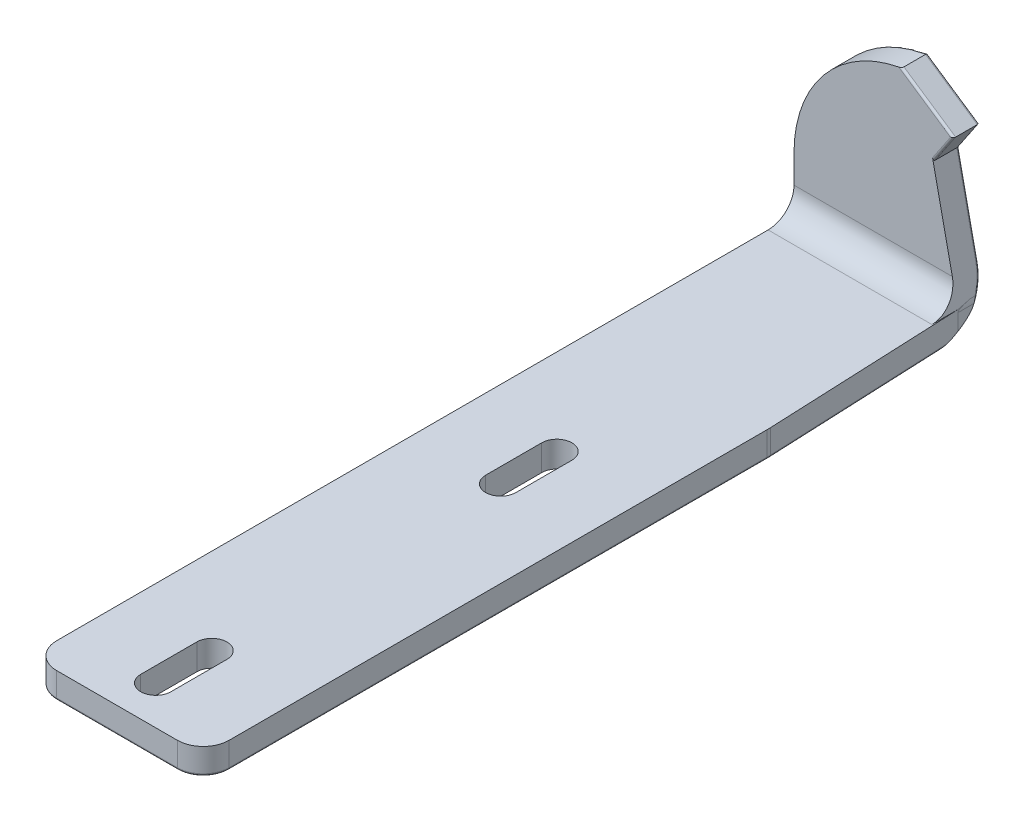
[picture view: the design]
ISO-10303-21;
HEADER;
FILE_DESCRIPTION(('STEP AP214'),'2;1');
FILE_NAME('part.step','',(''),(''),'','','');
FILE_SCHEMA(('AUTOMOTIVE_DESIGN { 1 0 10303 214 1 1 1 1 }'));
ENDSEC;
DATA;
#1=APPLICATION_CONTEXT('core data for automotive mechanical design processes');
#2=APPLICATION_PROTOCOL_DEFINITION('international standard','automotive_design',2000,#1);
#3=PRODUCT_CONTEXT('',#1,'mechanical');
#4=PRODUCT('Part','Part','',(#3));
#5=PRODUCT_RELATED_PRODUCT_CATEGORY('part','',(#4));
#6=PRODUCT_DEFINITION_FORMATION('','',#4);
#7=PRODUCT_DEFINITION_CONTEXT('part definition',#1,'design');
#8=PRODUCT_DEFINITION('design','',#6,#7);
#9=PRODUCT_DEFINITION_SHAPE('','',#8);
#10=(LENGTH_UNIT() NAMED_UNIT(*) SI_UNIT(.MILLI.,.METRE.));
#11=(NAMED_UNIT(*) PLANE_ANGLE_UNIT() SI_UNIT($,.RADIAN.));
#12=(NAMED_UNIT(*) SI_UNIT($,.STERADIAN.) SOLID_ANGLE_UNIT());
#13=UNCERTAINTY_MEASURE_WITH_UNIT(LENGTH_MEASURE(1.E-05),#10,'distance_accuracy_value','');
#14=(GEOMETRIC_REPRESENTATION_CONTEXT(3) GLOBAL_UNCERTAINTY_ASSIGNED_CONTEXT((#13)) GLOBAL_UNIT_ASSIGNED_CONTEXT((#10,
#11,#12)) REPRESENTATION_CONTEXT('',''));
#15=CARTESIAN_POINT('',(0.,0.,0.));
#16=DIRECTION('',(0.,0.,1.));
#17=DIRECTION('',(1.,0.,0.));
#18=AXIS2_PLACEMENT_3D('',#15,#16,#17);
#19=CARTESIAN_POINT('',(16.,2.68468729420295,3.));
#20=DIRECTION('',(0.,0.,-1.));
#21=DIRECTION('',(-1.,0.,0.));
#22=AXIS2_PLACEMENT_3D('',#19,#20,#21);
#23=CYLINDRICAL_SURFACE('',#22,3.);
#24=DIRECTION('',(0.,0.,-1.));
#25=VECTOR('',#24,1.);
#26=CARTESIAN_POINT('',(18.9344428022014,3.30842236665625,3.));
#27=LINE('',#26,#25);
#28=CARTESIAN_POINT('',(18.9344428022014,3.30842236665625,1.49849331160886));
#29=VERTEX_POINT('',#28);
#30=CARTESIAN_POINT('',(18.9344428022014,3.30842236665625,0.946743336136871));
#31=VERTEX_POINT('',#30);
#32=EDGE_CURVE('E540',#29,#31,#27,.T.);
#33=ORIENTED_EDGE('',*,*,#32,.F.);
#34=CARTESIAN_POINT('',(16.,2.68468729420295,-65.7112966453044));
#35=DIRECTION('',(-0.999048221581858,0.,0.0436193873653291));
#36=DIRECTION('',(-0.0436193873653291,0.,-0.999048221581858));
#37=AXIS2_PLACEMENT_3D('',#34,#35,#36);
#38=ELLIPSE('',#37,68.7767568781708,3.);
#39=CARTESIAN_POINT('',(19.,2.68468729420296,3.));
#40=VERTEX_POINT('',#39);
#41=EDGE_CURVE('E543',#29,#40,#38,.F.);
#42=ORIENTED_EDGE('',*,*,#41,.T.);
#43=DIRECTION('',(0.,0.,-1.));
#44=VECTOR('',#43,1.);
#45=CARTESIAN_POINT('',(19.,2.68468729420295,3.));
#46=LINE('',#45,#44);
#47=CARTESIAN_POINT('',(19.,2.68468729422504,1.12447066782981));
#48=VERTEX_POINT('',#47);
#49=EDGE_CURVE('E548',#48,#40,#46,.F.);
#50=ORIENTED_EDGE('',*,*,#49,.F.);
#51=CARTESIAN_POINT('',(17.1290818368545,11.8019779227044,6.));
#52=CARTESIAN_POINT('',(17.0869909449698,12.,6.));
#53=CARTESIAN_POINT('',(16.884544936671,12.,6.));
#54=CARTESIAN_POINT('',(17.1290818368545,11.8019779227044,5.74907725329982));
#55=CARTESIAN_POINT('',(17.0869909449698,12.,5.74004591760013));
#56=CARTESIAN_POINT('',(16.884544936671,12.,5.73816756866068));
#57=CARTESIAN_POINT('',(17.1325789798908,11.7855251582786,5.49815450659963));
#58=CARTESIAN_POINT('',(17.0905911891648,11.9830621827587,5.47996382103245));
#59=CARTESIAN_POINT('',(16.8880420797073,11.9828318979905,5.47633513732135));
#60=CARTESIAN_POINT('',(17.1465021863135,11.7200216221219,5.00060461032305));
#61=CARTESIAN_POINT('',(17.1049124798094,11.9156858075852,4.96442597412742));
#62=CARTESIAN_POINT('',(16.90196528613,11.9144803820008,4.95715263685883));
#63=CARTESIAN_POINT('',(17.1569335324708,11.670945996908,4.75398088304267));
#64=CARTESIAN_POINT('',(17.1156529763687,11.8651557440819,4.70872615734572));
#65=CARTESIAN_POINT('',(16.9123966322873,11.8632710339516,4.69980613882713));
#66=CARTESIAN_POINT('',(17.1845413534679,11.5410614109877,4.2692439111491));
#67=CARTESIAN_POINT('',(17.144057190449,11.7315244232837,4.20622729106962));
#68=CARTESIAN_POINT('',(16.9400044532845,11.7277392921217,4.19399364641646));
#69=CARTESIAN_POINT('',(17.2017277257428,11.4602058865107,4.03114371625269));
#70=CARTESIAN_POINT('',(17.1617582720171,11.648247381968,3.95921887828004));
#71=CARTESIAN_POINT('',(16.9571908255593,11.6433683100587,3.94554126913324));
#72=CARTESIAN_POINT('',(17.2425471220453,11.2681657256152,3.56751672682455));
#73=CARTESIAN_POINT('',(17.2037726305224,11.4505853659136,3.47821302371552));
#74=CARTESIAN_POINT('',(16.9980102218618,11.4429785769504,3.46175658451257));
#75=CARTESIAN_POINT('',(17.2661934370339,11.1569185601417,3.34201702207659));
#76=CARTESIAN_POINT('',(17.2281382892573,11.3359539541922,3.24406029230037));
#77=CARTESIAN_POINT('',(17.0216565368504,11.3268945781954,3.22645254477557));
#78=CARTESIAN_POINT('',(17.3195251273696,10.9060126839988,2.90743435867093));
#79=CARTESIAN_POINT('',(17.2830634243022,11.0775515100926,2.79264800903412));
#80=CARTESIAN_POINT('',(17.0749882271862,11.0650797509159,2.77297498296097));
#81=CARTESIAN_POINT('',(17.3492256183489,10.7662828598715,2.6983943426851));
#82=CARTESIAN_POINT('',(17.3136863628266,10.9334819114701,2.57530154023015));
#83=CARTESIAN_POINT('',(17.1046887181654,10.9192747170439,2.55484627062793));
#84=CARTESIAN_POINT('',(17.414156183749,10.4608085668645,2.30029166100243));
#85=CARTESIAN_POINT('',(17.3806078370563,10.6186411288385,2.16109729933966));
#86=CARTESIAN_POINT('',(17.1696192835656,10.6005189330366,2.13943477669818));
#87=CARTESIAN_POINT('',(17.4494015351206,10.2949922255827,2.11128667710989));
#88=CARTESIAN_POINT('',(17.4169763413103,10.447540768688,1.96422919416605));
#89=CARTESIAN_POINT('',(17.2048646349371,10.4274931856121,1.94221218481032));
#90=CARTESIAN_POINT('',(17.5248191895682,9.94018005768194,1.75647379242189));
#91=CARTESIAN_POINT('',(17.4947796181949,10.0815051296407,1.59423718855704));
#92=CARTESIAN_POINT('',(17.2802822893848,10.0572544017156,1.57197265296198));
#93=CARTESIAN_POINT('',(17.5650054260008,9.75111867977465,1.59073445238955));
#94=CARTESIAN_POINT('',(17.5362860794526,9.88623258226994,1.42118138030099));
#95=CARTESIAN_POINT('',(17.3204685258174,9.85997296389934,1.39902725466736));
#96=CARTESIAN_POINT('',(17.6496191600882,9.3530423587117,1.28527915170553));
#97=CARTESIAN_POINT('',(17.6236746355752,9.47510174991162,1.10168170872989));
#98=CARTESIAN_POINT('',(17.4050822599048,9.44458897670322,1.08029128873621));
#99=CARTESIAN_POINT('',(17.6940581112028,9.14397353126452,1.14563663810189));
#100=CARTESIAN_POINT('',(17.6696255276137,9.25891979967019,0.955380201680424));
#101=CARTESIAN_POINT('',(17.4495212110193,9.22643020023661,0.934577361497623));
#102=CARTESIAN_POINT('',(17.7864198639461,8.70944564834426,0.894761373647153));
#103=CARTESIAN_POINT('',(17.7651417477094,8.80955131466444,0.691827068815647));
#104=CARTESIAN_POINT('',(17.5418829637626,8.77300980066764,0.672794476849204));
#105=CARTESIAN_POINT('',(17.8343510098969,8.48394733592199,0.783599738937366));
#106=CARTESIAN_POINT('',(17.8147688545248,8.57607413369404,0.574782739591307));
#107=CARTESIAN_POINT('',(17.5898141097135,8.53770721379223,0.556799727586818));
#108=CARTESIAN_POINT('',(17.93288048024,8.02040262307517,0.591592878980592));
#109=CARTESIAN_POINT('',(17.9168173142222,8.09597387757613,0.371715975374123));
#110=CARTESIAN_POINT('',(17.6883435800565,8.05400838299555,0.356444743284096));
#111=CARTESIAN_POINT('',(17.9834839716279,7.7823319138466,0.510809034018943));
#112=CARTESIAN_POINT('',(17.9692900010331,7.84910929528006,0.285952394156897));
#113=CARTESIAN_POINT('',(17.7389470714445,7.80558677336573,0.272148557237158));
#114=CARTESIAN_POINT('',(18.0864956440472,7.29770009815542,0.380952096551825));
#115=CARTESIAN_POINT('',(18.076162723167,7.34631266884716,0.146923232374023));
#116=CARTESIAN_POINT('',(17.8419587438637,7.29988400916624,0.136645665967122));
#117=CARTESIAN_POINT('',(18.138906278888,7.0511274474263,0.331924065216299));
#118=CARTESIAN_POINT('',(18.1306010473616,7.09020048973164,0.0939517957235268));
#119=CARTESIAN_POINT('',(17.8943693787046,7.04259080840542,0.085485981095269));
#120=CARTESIAN_POINT('',(18.2446382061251,6.55369783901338,0.266436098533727));
#121=CARTESIAN_POINT('',(18.2405043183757,6.57314625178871,0.0214634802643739));
#122=CARTESIAN_POINT('',(18.0001013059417,6.52353382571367,0.0171507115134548));
#123=CARTESIAN_POINT('',(18.2979601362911,6.30283788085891,0.25));
#124=CARTESIAN_POINT('',(18.2959927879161,6.31209352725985,0.00225799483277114));
#125=CARTESIAN_POINT('',(18.0534232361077,6.26176691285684,0.));
#126=CARTESIAN_POINT('',(18.4046039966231,5.80111796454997,0.25));
#127=CARTESIAN_POINT('',(18.407075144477,5.78949212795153,-0.00227856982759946));
#128=CARTESIAN_POINT('',(18.1600670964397,5.73823308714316,0.));
#129=CARTESIAN_POINT('',(18.4579259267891,5.55025800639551,0.266436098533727));
#130=CARTESIAN_POINT('',(18.4626769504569,5.52790619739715,0.0127001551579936));
#131=CARTESIAN_POINT('',(18.2133890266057,5.47646617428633,0.0171507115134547));
#132=CARTESIAN_POINT('',(18.5636578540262,5.05282839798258,0.331924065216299));
#133=CARTESIAN_POINT('',(18.5730579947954,5.0086042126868,0.076404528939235));
#134=CARTESIAN_POINT('',(18.3191209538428,4.95740919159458,0.0854859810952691));
#135=CARTESIAN_POINT('',(18.6160684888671,4.80625574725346,0.380952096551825));
#136=CARTESIAN_POINT('',(18.6278295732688,4.75092419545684,0.125419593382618));
#137=CARTESIAN_POINT('',(18.3715315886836,4.70011599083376,0.136645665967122));
#138=CARTESIAN_POINT('',(18.7190801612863,4.32162393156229,0.510809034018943));
#139=CARTESIAN_POINT('',(18.7356293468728,4.24376613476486,0.256517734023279));
#140=CARTESIAN_POINT('',(18.4745432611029,4.19441322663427,0.272148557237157));
#141=CARTESIAN_POINT('',(18.7696836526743,4.08355322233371,0.591592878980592));
#142=CARTESIAN_POINT('',(18.7886351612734,3.99439338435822,0.3388518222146));
#143=CARTESIAN_POINT('',(18.5251467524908,3.94599161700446,0.356444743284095));
#144=CARTESIAN_POINT('',(18.8682131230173,3.62000850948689,0.783599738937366));
#145=CARTESIAN_POINT('',(18.8920038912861,3.50808174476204,0.535360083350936));
#146=CARTESIAN_POINT('',(18.6236762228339,3.46229278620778,0.556799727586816));
#147=CARTESIAN_POINT('',(18.9161442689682,3.39451019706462,0.894761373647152));
#148=CARTESIAN_POINT('',(18.9423313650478,3.27130959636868,0.649730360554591));
#149=CARTESIAN_POINT('',(18.6716073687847,3.22699019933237,0.672794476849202));
#150=CARTESIAN_POINT('',(19.0085060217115,2.95998231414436,1.14563663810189));
#151=CARTESIAN_POINT('',(19.0394794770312,2.81426366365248,0.908543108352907));
#152=CARTESIAN_POINT('',(18.763969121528,2.77356979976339,0.934577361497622));
#153=CARTESIAN_POINT('',(19.052944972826,2.75091348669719,1.28527915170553));
#154=CARTESIAN_POINT('',(19.0862540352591,2.59420666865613,1.05311256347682));
#155=CARTESIAN_POINT('',(18.8084080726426,2.55541102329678,1.08029128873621));
#156=CARTESIAN_POINT('',(19.1375587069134,2.35283716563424,1.59073445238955));
#157=CARTESIAN_POINT('',(19.1754823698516,2.17442035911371,1.37003190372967));
#158=CARTESIAN_POINT('',(18.89302180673,2.14002703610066,1.39902725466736));
#159=CARTESIAN_POINT('',(19.177744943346,2.16377578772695,1.75647379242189));
#160=CARTESIAN_POINT('',(19.2178825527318,1.97494318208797,1.54242861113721));
#161=CARTESIAN_POINT('',(18.9332080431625,1.94274559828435,1.57197265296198));
#162=CARTESIAN_POINT('',(19.2531625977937,1.80896361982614,2.11128667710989));
#163=CARTESIAN_POINT('',(19.2976126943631,1.59984235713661,1.91221077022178));
#164=CARTESIAN_POINT('',(19.0086256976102,1.57250681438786,1.94221218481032));
#165=CARTESIAN_POINT('',(19.2884079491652,1.64314727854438,2.30029166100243));
#166=CARTESIAN_POINT('',(19.3348852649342,1.42448869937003,2.10955596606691));
#167=CARTESIAN_POINT('',(19.0438710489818,1.39948106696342,2.13943477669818));
#168=CARTESIAN_POINT('',(19.3533385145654,1.33767298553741,2.6983943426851));
#169=CARTESIAN_POINT('',(19.4036897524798,1.10078903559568,2.52597655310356));
#170=CARTESIAN_POINT('',(19.1088016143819,1.08072528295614,2.55484627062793));
#171=CARTESIAN_POINT('',(19.3830390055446,1.19794316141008,2.90743435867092));
#172=CARTESIAN_POINT('',(19.4351646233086,0.952711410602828,2.74492276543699));
#173=CARTESIAN_POINT('',(19.1385021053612,0.934920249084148,2.77297498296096));
#174=CARTESIAN_POINT('',(19.4363706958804,0.947037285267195,3.34201702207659));
#175=CARTESIAN_POINT('',(19.4917965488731,0.686279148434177,3.200863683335));
#176=CARTESIAN_POINT('',(19.1918337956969,0.673105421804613,3.22645254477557));
#177=CARTESIAN_POINT('',(19.460017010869,0.835790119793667,3.56751672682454));
#178=CARTESIAN_POINT('',(19.5169011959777,0.568171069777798,3.43764427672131));
#179=CARTESIAN_POINT('',(19.2154801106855,0.557021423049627,3.46175658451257));
#180=CARTESIAN_POINT('',(19.5008364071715,0.643749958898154,4.03114371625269));
#181=CARTESIAN_POINT('',(19.5603223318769,0.363890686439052,3.92520493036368));
#182=CARTESIAN_POINT('',(19.256299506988,0.356631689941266,3.94554126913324));
#183=CARTESIAN_POINT('',(19.5180227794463,0.562894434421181,4.2692439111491));
#184=CARTESIAN_POINT('',(19.5785951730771,0.277923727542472,4.17569613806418));
#185=CARTESIAN_POINT('',(19.2734858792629,0.272260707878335,4.19399364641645));
#186=CARTESIAN_POINT('',(19.5456306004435,0.433009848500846,4.75398088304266));
#187=CARTESIAN_POINT('',(19.6080013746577,0.139578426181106,4.68633047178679));
#188=CARTESIAN_POINT('',(19.30109370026,0.13672896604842,4.69980613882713));
#189=CARTESIAN_POINT('',(19.5560619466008,0.383934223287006,5.00060461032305));
#190=CARTESIAN_POINT('',(19.6191034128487,0.0873474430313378,4.94612616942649));
#191=CARTESIAN_POINT('',(19.3115250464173,0.0855196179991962,4.95715263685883));
#192=CARTESIAN_POINT('',(19.5699851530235,0.318430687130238,5.49815450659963));
#193=CARTESIAN_POINT('',(19.6339457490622,0.0175197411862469,5.47080484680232));
#194=CARTESIAN_POINT('',(19.32544825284,0.0171681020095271,5.47633513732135));
#195=CARTESIAN_POINT('',(19.5734822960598,0.301977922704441,5.74907725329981));
#196=CARTESIAN_POINT('',(19.6376696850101,0.,5.73530300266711));
#197=CARTESIAN_POINT('',(19.3289453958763,0.,5.73816756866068));
#198=CARTESIAN_POINT('',(19.5734822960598,0.301977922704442,6.25092274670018));
#199=CARTESIAN_POINT('',(19.6376696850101,0.,6.26469699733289));
#200=CARTESIAN_POINT('',(19.3289453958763,0.,6.26183243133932));
#201=CARTESIAN_POINT('',(19.5699851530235,0.318430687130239,6.50184549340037));
#202=CARTESIAN_POINT('',(19.6339457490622,0.0175197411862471,6.52919515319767));
#203=CARTESIAN_POINT('',(19.32544825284,0.0171681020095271,6.52366486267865));
#204=CARTESIAN_POINT('',(19.5560619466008,0.383934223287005,6.99939538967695));
#205=CARTESIAN_POINT('',(19.6191034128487,0.0873474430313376,7.05387383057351));
#206=CARTESIAN_POINT('',(19.3115250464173,0.0855196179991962,7.04284736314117));
#207=CARTESIAN_POINT('',(19.5456306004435,0.433009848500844,7.24601911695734));
#208=CARTESIAN_POINT('',(19.6080013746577,0.139578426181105,7.31366952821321));
#209=CARTESIAN_POINT('',(19.30109370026,0.13672896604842,7.30019386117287));
#210=CARTESIAN_POINT('',(19.5180227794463,0.562894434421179,7.7307560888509));
#211=CARTESIAN_POINT('',(19.5785951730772,0.277923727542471,7.82430386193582));
#212=CARTESIAN_POINT('',(19.2734858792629,0.272260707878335,7.80600635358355));
#213=CARTESIAN_POINT('',(19.5008364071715,0.643749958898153,7.96885628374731));
#214=CARTESIAN_POINT('',(19.5603223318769,0.363890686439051,8.07479506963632));
#215=CARTESIAN_POINT('',(19.256299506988,0.356631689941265,8.05445873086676));
#216=CARTESIAN_POINT('',(19.460017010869,0.835790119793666,8.43248327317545));
#217=CARTESIAN_POINT('',(19.5169011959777,0.568171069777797,8.56235572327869));
#218=CARTESIAN_POINT('',(19.2154801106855,0.557021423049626,8.53824341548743));
#219=CARTESIAN_POINT('',(19.4363706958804,0.947037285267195,8.65798297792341));
#220=CARTESIAN_POINT('',(19.4917965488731,0.686279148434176,8.799136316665));
#221=CARTESIAN_POINT('',(19.1918337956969,0.673105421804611,8.77354745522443));
#222=CARTESIAN_POINT('',(19.3830390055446,1.19794316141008,9.09256564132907));
#223=CARTESIAN_POINT('',(19.4351646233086,0.952711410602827,9.25507723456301));
#224=CARTESIAN_POINT('',(19.1385021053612,0.934920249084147,9.22702501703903));
#225=CARTESIAN_POINT('',(19.3533385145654,1.33767298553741,9.3016056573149));
#226=CARTESIAN_POINT('',(19.4036897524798,1.10078903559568,9.47402344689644));
#227=CARTESIAN_POINT('',(19.1088016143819,1.08072528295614,9.44515372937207));
#228=CARTESIAN_POINT('',(19.2884079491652,1.64314727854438,9.69970833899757));
#229=CARTESIAN_POINT('',(19.3348852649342,1.42448869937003,9.89044403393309));
#230=CARTESIAN_POINT('',(19.0438710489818,1.39948106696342,9.86056522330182));
#231=CARTESIAN_POINT('',(19.2531625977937,1.80896361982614,9.88871332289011));
#232=CARTESIAN_POINT('',(19.2976126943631,1.59984235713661,10.0877892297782));
#233=CARTESIAN_POINT('',(19.0086256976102,1.57250681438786,10.0577878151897));
#234=CARTESIAN_POINT('',(19.177744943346,2.16377578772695,10.2435262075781));
#235=CARTESIAN_POINT('',(19.2178825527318,1.97494318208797,10.4575713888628));
#236=CARTESIAN_POINT('',(18.9332080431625,1.94274559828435,10.428027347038));
#237=CARTESIAN_POINT('',(19.1375587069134,2.35283716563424,10.4092655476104));
#238=CARTESIAN_POINT('',(19.1754823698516,2.17442035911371,10.6299680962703));
#239=CARTESIAN_POINT('',(18.89302180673,2.14002703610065,10.6009727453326));
#240=CARTESIAN_POINT('',(19.052944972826,2.75091348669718,10.7147208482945));
#241=CARTESIAN_POINT('',(19.0862540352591,2.59420666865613,10.9468874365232));
#242=CARTESIAN_POINT('',(18.8084080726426,2.55541102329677,10.9197087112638));
#243=CARTESIAN_POINT('',(19.0085060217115,2.95998231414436,10.8543633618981));
#244=CARTESIAN_POINT('',(19.0394794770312,2.81426366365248,11.0914568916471));
#245=CARTESIAN_POINT('',(18.763969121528,2.77356979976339,11.0654226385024));
#246=CARTESIAN_POINT('',(18.9161442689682,3.39451019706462,11.1052386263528));
#247=CARTESIAN_POINT('',(18.9423313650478,3.27130959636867,11.3502696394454));
#248=CARTESIAN_POINT('',(18.6716073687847,3.22699019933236,11.3272055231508));
#249=CARTESIAN_POINT('',(18.8682131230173,3.62000850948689,11.2164002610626));
#250=CARTESIAN_POINT('',(18.8920038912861,3.50808174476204,11.4646399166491));
#251=CARTESIAN_POINT('',(18.6236762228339,3.46229278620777,11.4432002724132));
#252=CARTESIAN_POINT('',(18.7696836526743,4.08355322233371,11.4084071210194));
#253=CARTESIAN_POINT('',(18.7886351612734,3.99439338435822,11.6611481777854));
#254=CARTESIAN_POINT('',(18.5251467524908,3.94599161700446,11.6435552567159));
#255=CARTESIAN_POINT('',(18.7190801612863,4.32162393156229,11.4891909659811));
#256=CARTESIAN_POINT('',(18.7356293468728,4.24376613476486,11.7434822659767));
#257=CARTESIAN_POINT('',(18.4745432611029,4.19441322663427,11.7278514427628));
#258=CARTESIAN_POINT('',(18.6160684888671,4.80625574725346,11.6190479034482));
#259=CARTESIAN_POINT('',(18.6278295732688,4.75092419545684,11.8745804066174));
#260=CARTESIAN_POINT('',(18.3715315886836,4.70011599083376,11.8633543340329));
#261=CARTESIAN_POINT('',(18.5636578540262,5.05282839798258,11.6680759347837));
#262=CARTESIAN_POINT('',(18.5730579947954,5.0086042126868,11.9235954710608));
#263=CARTESIAN_POINT('',(18.3191209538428,4.95740919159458,11.9145140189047));
#264=CARTESIAN_POINT('',(18.4579259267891,5.55025800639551,11.7335639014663));
#265=CARTESIAN_POINT('',(18.4626769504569,5.52790619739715,11.987299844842));
#266=CARTESIAN_POINT('',(18.2133890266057,5.47646617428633,11.9828492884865));
#267=CARTESIAN_POINT('',(18.4046039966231,5.80111796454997,11.75));
#268=CARTESIAN_POINT('',(18.407075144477,5.78949212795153,12.0022785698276));
#269=CARTESIAN_POINT('',(18.1600670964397,5.73823308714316,12.));
#270=CARTESIAN_POINT('',(18.2979601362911,6.30283788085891,11.75));
#271=CARTESIAN_POINT('',(18.2959927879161,6.31209352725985,11.9977420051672));
#272=CARTESIAN_POINT('',(18.0534232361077,6.26176691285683,12.));
#273=CARTESIAN_POINT('',(18.2446382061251,6.55369783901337,11.7335639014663));
#274=CARTESIAN_POINT('',(18.2405043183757,6.57314625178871,11.9785365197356));
#275=CARTESIAN_POINT('',(18.0001013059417,6.52353382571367,11.9828492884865));
#276=CARTESIAN_POINT('',(18.138906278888,7.0511274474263,11.6680759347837));
#277=CARTESIAN_POINT('',(18.1306010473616,7.09020048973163,11.9060482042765));
#278=CARTESIAN_POINT('',(17.8943693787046,7.04259080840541,11.9145140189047));
#279=CARTESIAN_POINT('',(18.0864956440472,7.29770009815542,11.6190479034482));
#280=CARTESIAN_POINT('',(18.076162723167,7.34631266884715,11.853076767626));
#281=CARTESIAN_POINT('',(17.8419587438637,7.29988400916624,11.8633543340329));
#282=CARTESIAN_POINT('',(17.9834839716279,7.78233191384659,11.4891909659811));
#283=CARTESIAN_POINT('',(17.9692900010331,7.84910929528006,11.7140476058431));
#284=CARTESIAN_POINT('',(17.7389470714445,7.80558677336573,11.7278514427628));
#285=CARTESIAN_POINT('',(17.93288048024,8.02040262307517,11.4084071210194));
#286=CARTESIAN_POINT('',(17.9168173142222,8.09597387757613,11.6282840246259));
#287=CARTESIAN_POINT('',(17.6883435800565,8.05400838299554,11.6435552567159));
#288=CARTESIAN_POINT('',(17.8343510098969,8.48394733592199,11.2164002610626));
#289=CARTESIAN_POINT('',(17.8147688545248,8.57607413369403,11.4252172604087));
#290=CARTESIAN_POINT('',(17.5898141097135,8.53770721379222,11.4432002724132));
#291=CARTESIAN_POINT('',(17.7864198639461,8.70944564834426,11.1052386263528));
#292=CARTESIAN_POINT('',(17.7651417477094,8.80955131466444,11.3081729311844));
#293=CARTESIAN_POINT('',(17.5418829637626,8.77300980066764,11.3272055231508));
#294=CARTESIAN_POINT('',(17.6940581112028,9.14397353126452,10.8543633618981));
#295=CARTESIAN_POINT('',(17.6696255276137,9.25891979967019,11.0446197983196));
#296=CARTESIAN_POINT('',(17.4495212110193,9.22643020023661,11.0654226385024));
#297=CARTESIAN_POINT('',(17.6496191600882,9.35304235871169,10.7147208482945));
#298=CARTESIAN_POINT('',(17.6236746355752,9.47510174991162,10.8983182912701));
#299=CARTESIAN_POINT('',(17.4050822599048,9.44458897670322,10.9197087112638));
#300=CARTESIAN_POINT('',(17.5650054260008,9.75111867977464,10.4092655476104));
#301=CARTESIAN_POINT('',(17.5362860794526,9.88623258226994,10.578818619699));
#302=CARTESIAN_POINT('',(17.3204685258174,9.85997296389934,10.6009727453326));
#303=CARTESIAN_POINT('',(17.5248191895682,9.94018005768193,10.2435262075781));
#304=CARTESIAN_POINT('',(17.4947796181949,10.0815051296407,10.405762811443));
#305=CARTESIAN_POINT('',(17.2802822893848,10.0572544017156,10.428027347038));
#306=CARTESIAN_POINT('',(17.4494015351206,10.2949922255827,9.88871332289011));
#307=CARTESIAN_POINT('',(17.4169763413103,10.447540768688,10.035770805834));
#308=CARTESIAN_POINT('',(17.2048646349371,10.4274931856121,10.0577878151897));
#309=CARTESIAN_POINT('',(17.414156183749,10.4608085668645,9.69970833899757));
#310=CARTESIAN_POINT('',(17.3806078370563,10.6186411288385,9.83890270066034));
#311=CARTESIAN_POINT('',(17.1696192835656,10.6005189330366,9.86056522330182));
#312=CARTESIAN_POINT('',(17.3492256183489,10.7662828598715,9.30160565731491));
#313=CARTESIAN_POINT('',(17.3136863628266,10.93348191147,9.42469845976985));
#314=CARTESIAN_POINT('',(17.1046887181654,10.9192747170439,9.44515372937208));
#315=CARTESIAN_POINT('',(17.3195251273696,10.9060126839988,9.09256564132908));
#316=CARTESIAN_POINT('',(17.2830634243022,11.0775515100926,9.20735199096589));
#317=CARTESIAN_POINT('',(17.0749882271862,11.0650797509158,9.22702501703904));
#318=CARTESIAN_POINT('',(17.2661934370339,11.1569185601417,8.65798297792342));
#319=CARTESIAN_POINT('',(17.2281382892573,11.3359539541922,8.75593970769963));
#320=CARTESIAN_POINT('',(17.0216565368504,11.3268945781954,8.77354745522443));
#321=CARTESIAN_POINT('',(17.2425471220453,11.2681657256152,8.43248327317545));
#322=CARTESIAN_POINT('',(17.2037726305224,11.4505853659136,8.52178697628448));
#323=CARTESIAN_POINT('',(16.9980102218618,11.4429785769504,8.53824341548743));
#324=CARTESIAN_POINT('',(17.2017277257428,11.4602058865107,7.96885628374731));
#325=CARTESIAN_POINT('',(17.1617582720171,11.648247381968,8.04078112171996));
#326=CARTESIAN_POINT('',(16.9571908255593,11.6433683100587,8.05445873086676));
#327=CARTESIAN_POINT('',(17.1845413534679,11.5410614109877,7.7307560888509));
#328=CARTESIAN_POINT('',(17.144057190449,11.7315244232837,7.79377270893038));
#329=CARTESIAN_POINT('',(16.9400044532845,11.7277392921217,7.80600635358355));
#330=CARTESIAN_POINT('',(17.1569335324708,11.670945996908,7.24601911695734));
#331=CARTESIAN_POINT('',(17.1156529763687,11.8651557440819,7.29127384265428));
#332=CARTESIAN_POINT('',(16.9123966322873,11.8632710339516,7.30019386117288));
#333=CARTESIAN_POINT('',(17.1465021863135,11.7200216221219,6.99939538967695));
#334=CARTESIAN_POINT('',(17.1049124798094,11.9156858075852,7.03557402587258));
#335=CARTESIAN_POINT('',(16.90196528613,11.9144803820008,7.04284736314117));
#336=CARTESIAN_POINT('',(17.1325789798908,11.7855251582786,6.50184549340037));
#337=CARTESIAN_POINT('',(17.0905911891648,11.9830621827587,6.52003617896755));
#338=CARTESIAN_POINT('',(16.8880420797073,11.9828318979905,6.52366486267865));
#339=CARTESIAN_POINT('',(17.1290818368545,11.8019779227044,6.25092274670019));
#340=CARTESIAN_POINT('',(17.0869909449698,12.,6.25995408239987));
#341=CARTESIAN_POINT('',(16.884544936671,12.,6.26183243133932));
#342=CARTESIAN_POINT('',(17.1290818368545,11.8019779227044,6.));
#343=CARTESIAN_POINT('',(17.0869909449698,12.,6.));
#344=CARTESIAN_POINT('',(16.884544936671,12.,6.));
#345=(BOUNDED_SURFACE() B_SPLINE_SURFACE(3,2,((#51,#52,#53),(#54,#55,#56),(#57,#58,#59),(#60,
#61,#62),(#63,#64,#65),(#66,#67,#68),(#69,#70,#71),(#72,#73,#74),(#75,#76,#77),(#78,#79,#80),
(#81,#82,#83),(#84,#85,#86),(#87,#88,#89),(#90,#91,#92),(#93,#94,#95),(#96,#97,#98),(#99,#100,
#101),(#102,#103,#104),(#105,#106,#107),(#108,#109,#110),(#111,#112,#113),(#114,#115,#116),
(#117,#118,#119),(#120,#121,#122),(#123,#124,#125),(#126,#127,#128),(#129,#130,#131),(#132,#133,
#134),(#135,#136,#137),(#138,#139,#140),(#141,#142,#143),(#144,#145,#146),(#147,#148,#149),
(#150,#151,#152),(#153,#154,#155),(#156,#157,#158),(#159,#160,#161),(#162,#163,#164),(#165,#166,
#167),(#168,#169,#170),(#171,#172,#173),(#174,#175,#176),(#177,#178,#179),(#180,#181,#182),
(#183,#184,#185),(#186,#187,#188),(#189,#190,#191),(#192,#193,#194),(#195,#196,#197),(#198,#199,
#200),(#201,#202,#203),(#204,#205,#206),(#207,#208,#209),(#210,#211,#212),(#213,#214,#215),
(#216,#217,#218),(#219,#220,#221),(#222,#223,#224),(#225,#226,#227),(#228,#229,#230),(#231,#232,
#233),(#234,#235,#236),(#237,#238,#239),(#240,#241,#242),(#243,#244,#245),(#246,#247,#248),
(#249,#250,#251),(#252,#253,#254),(#255,#256,#257),(#258,#259,#260),(#261,#262,#263),(#264,#265,
#266),(#267,#268,#269),(#270,#271,#272),(#273,#274,#275),(#276,#277,#278),(#279,#280,#281),
(#282,#283,#284),(#285,#286,#287),(#288,#289,#290),(#291,#292,#293),(#294,#295,#296),(#297,#298,
#299),(#300,#301,#302),(#303,#304,#305),(#306,#307,#308),(#309,#310,#311),(#312,#313,#314),
(#315,#316,#317),(#318,#319,#320),(#321,#322,#323),(#324,#325,#326),(#327,#328,#329),(#330,#331,
#332),(#333,#334,#335),(#336,#337,#338),(#339,#340,#341),(#342,#343,#344)),.UNSPECIFIED.,.T.,
.F.,.F.) B_SPLINE_SURFACE_WITH_KNOTS((4,2,2,2,2,2,2,2,2,2,2,2,2,2,2,2,2,2,2,2,2,2,2,2,2,2,2,2,2,
2,2,2,2,2,2,2,2,2,2,2,2,2,2,2,2,2,2,2,4),(3,3),(0.,0.752208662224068,1.50499104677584,
2.25888054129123,3.01433295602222,3.77169515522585,4.53118177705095,5.29286152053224,
6.05665367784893,6.822334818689,7.58955485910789,8.35786120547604,9.12672926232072,
9.89559731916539,10.6639036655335,11.4311237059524,12.1968048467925,12.9605970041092,
13.7222767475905,14.4817633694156,15.2391255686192,15.9945779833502,16.7484674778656,
17.5012498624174,18.2534585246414,19.0056671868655,19.7584495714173,20.5123390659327,
21.2677914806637,22.0251536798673,22.7846403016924,23.5463200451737,24.3101122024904,
25.0757933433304,25.8430133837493,26.6113197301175,27.3801877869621,28.1490558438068,
28.917362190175,29.6845822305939,30.4502633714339,31.2140555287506,31.9757352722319,
32.735221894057,33.4925840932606,34.2480365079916,35.001926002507,35.7547083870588,
36.5069170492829),(0.,1.),
.UNSPECIFIED.) GEOMETRIC_REPRESENTATION_ITEM() RATIONAL_B_SPLINE_SURFACE(((1.,0.777145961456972,
1.),(1.,0.777145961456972,1.),(1.,0.776954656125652,1.),(1.,0.776192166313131,1.),(1.,
0.775620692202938,1.),(1.,0.774105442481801,1.),(1.,0.773161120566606,1.),(1.,0.770912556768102,
1.),(1.,0.769607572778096,1.),(1.,0.766654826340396,1.),(1.,0.76500620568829,1.),(1.,
0.761388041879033,1.),(1.,0.759417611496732,1.),(1.,0.755182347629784,1.),(1.,0.75291668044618,
1.),(1.,0.748122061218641,1.),(1.,0.745592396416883,1.),(1.,0.740305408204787,1.),(1.,
0.737547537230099,1.),(1.,0.731844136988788,1.),(1.,0.728898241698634,1.),(1.,0.722862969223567,
1.),(1.,0.71977339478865,1.),(1.,0.713498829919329,1.),(1.,0.710313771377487,1.),(1.,
0.703899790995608,1.),(1.,0.700670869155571,1.),(1.,0.694223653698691,1.),(1.,0.691005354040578,
1.),(1.,0.684636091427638,1.),(1.,0.681485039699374,1.),(1.,0.675308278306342,1.),(1.,
0.672282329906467,1.),(1.,0.666413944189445,1.),(1.,0.663571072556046,1.),(1.,0.658125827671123,
1.),(1.,0.655522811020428,1.),(1.,0.650611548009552,1.),(1.,0.648302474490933,1.),(1.,
0.644028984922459,1.),(1.,0.642063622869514,1.),(1.,0.638521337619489,1.),(1.,0.636943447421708,
1.),(1.,0.634212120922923,1.),(1.,0.63305781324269,1.),(1.,0.631200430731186,1.),(1.,
0.630496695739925,1.),(1.,0.629556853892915,1.),(1.,0.629320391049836,1.),(1.,0.629320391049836,
1.),(1.,0.629556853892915,1.),(1.,0.630496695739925,1.),(1.,0.631200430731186,1.),(1.,
0.63305781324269,1.),(1.,0.634212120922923,1.),(1.,0.636943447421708,1.),(1.,0.638521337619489,
1.),(1.,0.642063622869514,1.),(1.,0.644028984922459,1.),(1.,0.648302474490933,1.),(1.,
0.650611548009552,1.),(1.,0.655522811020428,1.),(1.,0.658125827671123,1.),(1.,0.663571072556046,
1.),(1.,0.666413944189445,1.),(1.,0.672282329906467,1.),(1.,0.675308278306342,1.),(1.,
0.681485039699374,1.),(1.,0.684636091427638,1.),(1.,0.691005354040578,1.),(1.,0.694223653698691,
1.),(1.,0.700670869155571,1.),(1.,0.703899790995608,1.),(1.,0.710313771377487,1.),(1.,
0.713498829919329,1.),(1.,0.71977339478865,1.),(1.,0.722862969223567,1.),(1.,0.728898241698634,
1.),(1.,0.731844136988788,1.),(1.,0.737547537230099,1.),(1.,0.740305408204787,1.),(1.,
0.745592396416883,1.),(1.,0.748122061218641,1.),(1.,0.752916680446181,1.),(1.,0.755182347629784,
1.),(1.,0.759417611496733,1.),(1.,0.761388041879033,1.),(1.,0.76500620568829,1.),(1.,
0.766654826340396,1.),(1.,0.769607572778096,1.),(1.,0.770912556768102,1.),(1.,0.773161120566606,
1.),(1.,0.774105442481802,1.),(1.,0.775620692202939,1.),(1.,0.776192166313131,1.),(1.,
0.776954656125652,1.),(1.,0.777145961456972,1.),(1.,0.777145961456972,1.))) REPRESENTATION_ITEM('') SURFACE());
#346=CARTESIAN_POINT('',(19.,2.68468729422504,1.12447066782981));
#347=CARTESIAN_POINT('',(19.0000017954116,2.72391872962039,1.10937180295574));
#348=CARTESIAN_POINT('',(18.9992300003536,2.76345497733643,1.09510233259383));
#349=CARTESIAN_POINT('',(18.9960852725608,2.84297399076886,1.06808608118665));
#350=CARTESIAN_POINT('',(18.9937126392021,2.88295667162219,1.05533901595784));
#351=CARTESIAN_POINT('',(18.9841284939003,3.00314716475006,1.01923093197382));
#352=CARTESIAN_POINT('',(18.9744512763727,3.08379923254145,0.997927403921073));
#353=CARTESIAN_POINT('',(18.9542535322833,3.2085114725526,0.968321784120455));
#354=CARTESIAN_POINT('',(18.9460941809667,3.25262263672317,0.958497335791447));
#355=CARTESIAN_POINT('',(18.9361046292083,3.30056528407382,0.948387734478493));
#356=CARTESIAN_POINT('',(18.9352777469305,3.30449424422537,0.947563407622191));
#357=CARTESIAN_POINT('',(18.9344428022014,3.30842236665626,0.946743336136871));
#358=B_SPLINE_CURVE_WITH_KNOTS('',3,(#346,#347,#348,#349,#350,#351,#352,#353,#354,#355,#356,
#357),.UNSPECIFIED.,.F.,.F.,(4,2,2,2,2,4),(0.,0.126069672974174,0.252115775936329,
0.503564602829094,0.641282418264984,0.65357871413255),.UNSPECIFIED.);
#359=EDGE_CURVE('E545',#31,#48,#358,.F.);
#360=ORIENTED_EDGE('',*,*,#359,.F.);
#361=EDGE_LOOP('',(#33,#42,#50,#360));
#362=FACE_BOUND('',#361,.T.);
#363=ADVANCED_FACE('F34',(#362),#23,.T.);
#364=CARTESIAN_POINT('',(0.,0.,3.));
#365=DIRECTION('',(0.,1.,0.));
#366=DIRECTION('',(0.,0.,1.));
#367=AXIS2_PLACEMENT_3D('',#364,#365,#366);
#368=PLANE('',#367);
#369=DIRECTION('',(0.,0.,1.));
#370=VECTOR('',#369,1.);
#371=CARTESIAN_POINT('',(8.24999999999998,0.,87.));
#372=LINE('',#371,#370);
#373=CARTESIAN_POINT('',(8.24999999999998,0.,80.5));
#374=VERTEX_POINT('',#373);
#375=CARTESIAN_POINT('',(8.24999999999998,0.,87.));
#376=VERTEX_POINT('',#375);
#377=EDGE_CURVE('E284',#374,#376,#372,.T.);
#378=ORIENTED_EDGE('',*,*,#377,.T.);
#379=CARTESIAN_POINT('',(9.99999999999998,0.,87.));
#380=DIRECTION('',(0.,1.,0.));
#381=DIRECTION('',(-1.,0.,0.));
#382=AXIS2_PLACEMENT_3D('',#379,#380,#381);
#383=CIRCLE('',#382,1.75);
#384=CARTESIAN_POINT('',(11.75,0.,87.));
#385=VERTEX_POINT('',#384);
#386=EDGE_CURVE('E275',#376,#385,#383,.T.);
#387=ORIENTED_EDGE('',*,*,#386,.T.);
#388=DIRECTION('',(0.,0.,-1.));
#389=VECTOR('',#388,1.);
#390=CARTESIAN_POINT('',(11.75,0.,80.5));
#391=LINE('',#390,#389);
#392=CARTESIAN_POINT('',(11.75,0.,80.5));
#393=VERTEX_POINT('',#392);
#394=EDGE_CURVE('E281',#385,#393,#391,.T.);
#395=ORIENTED_EDGE('',*,*,#394,.T.);
#396=CARTESIAN_POINT('',(9.99999999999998,0.,80.5));
#397=DIRECTION('',(0.,1.,0.));
#398=DIRECTION('',(-1.,0.,0.));
#399=AXIS2_PLACEMENT_3D('',#396,#397,#398);
#400=CIRCLE('',#399,1.75);
#401=EDGE_CURVE('E49',#393,#374,#400,.T.);
#402=ORIENTED_EDGE('',*,*,#401,.T.);
#403=EDGE_LOOP('',(#378,#387,#395,#402));
#404=FACE_BOUND('',#403,.T.);
#405=DIRECTION('',(0.,0.,1.));
#406=VECTOR('',#405,1.);
#407=CARTESIAN_POINT('',(8.24999999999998,0.,47.));
#408=LINE('',#407,#406);
#409=CARTESIAN_POINT('',(8.24999999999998,0.,40.5));
#410=VERTEX_POINT('',#409);
#411=CARTESIAN_POINT('',(8.24999999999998,0.,47.));
#412=VERTEX_POINT('',#411);
#413=EDGE_CURVE('E311',#410,#412,#408,.T.);
#414=ORIENTED_EDGE('',*,*,#413,.T.);
#415=CARTESIAN_POINT('',(9.99999999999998,0.,47.));
#416=DIRECTION('',(0.,1.,0.));
#417=DIRECTION('',(-1.,0.,0.));
#418=AXIS2_PLACEMENT_3D('',#415,#416,#417);
#419=CIRCLE('',#418,1.75);
#420=CARTESIAN_POINT('',(11.75,0.,47.));
#421=VERTEX_POINT('',#420);
#422=EDGE_CURVE('E302',#412,#421,#419,.T.);
#423=ORIENTED_EDGE('',*,*,#422,.T.);
#424=DIRECTION('',(0.,0.,-1.));
#425=VECTOR('',#424,1.);
#426=CARTESIAN_POINT('',(11.75,0.,40.5));
#427=LINE('',#426,#425);
#428=CARTESIAN_POINT('',(11.75,0.,40.5));
#429=VERTEX_POINT('',#428);
#430=EDGE_CURVE('E305',#421,#429,#427,.T.);
#431=ORIENTED_EDGE('',*,*,#430,.T.);
#432=CARTESIAN_POINT('',(9.99999999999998,0.,40.5));
#433=DIRECTION('',(0.,1.,0.));
#434=DIRECTION('',(-1.,0.,0.));
#435=AXIS2_PLACEMENT_3D('',#432,#433,#434);
#436=CIRCLE('',#435,1.75);
#437=EDGE_CURVE('E308',#429,#410,#436,.T.);
#438=ORIENTED_EDGE('',*,*,#437,.T.);
#439=EDGE_LOOP('',(#414,#423,#431,#438));
#440=FACE_BOUND('',#439,.T.);
#441=DIRECTION('',(1.,0.,0.));
#442=VECTOR('',#441,1.);
#443=CARTESIAN_POINT('',(19.,0.,6.));
#444=LINE('',#443,#442);
#445=CARTESIAN_POINT('',(0.25,0.,6.));
#446=VERTEX_POINT('',#445);
#447=CARTESIAN_POINT('',(18.8807446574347,0.,6.));
#448=VERTEX_POINT('',#447);
#449=EDGE_CURVE('E449',#446,#448,#444,.T.);
#450=ORIENTED_EDGE('',*,*,#449,.T.);
#451=DIRECTION('',(0.0436193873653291,0.,0.999048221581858));
#452=VECTOR('',#451,1.);
#453=CARTESIAN_POINT('',(18.7140875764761,0.,2.18292529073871));
#454=LINE('',#453,#452);
#455=CARTESIAN_POINT('',(19.7407201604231,0.,25.6966772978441));
#456=VERTEX_POINT('',#455);
#457=EDGE_CURVE('E472',#448,#456,#454,.T.);
#458=ORIENTED_EDGE('',*,*,#457,.T.);
#459=CARTESIAN_POINT('',(10.,0.,26.121966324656));
#460=DIRECTION('',(0.,1.,0.));
#461=DIRECTION('',(0.,0.,1.));
#462=AXIS2_PLACEMENT_3D('',#459,#460,#461);
#463=CIRCLE('',#462,9.75);
#464=CARTESIAN_POINT('',(19.75,0.,26.121966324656));
#465=VERTEX_POINT('',#464);
#466=EDGE_CURVE('E470',#456,#465,#463,.F.);
#467=ORIENTED_EDGE('',*,*,#466,.T.);
#468=DIRECTION('',(0.,0.,-1.));
#469=VECTOR('',#468,1.);
#470=CARTESIAN_POINT('',(19.75,0.,88.5));
#471=LINE('',#470,#469);
#472=CARTESIAN_POINT('',(19.75,0.,88.5));
#473=VERTEX_POINT('',#472);
#474=EDGE_CURVE('E468',#465,#473,#471,.F.);
#475=ORIENTED_EDGE('',*,*,#474,.T.);
#476=CARTESIAN_POINT('',(17.,0.,88.5));
#477=DIRECTION('',(0.,1.,0.));
#478=DIRECTION('',(0.,0.,1.));
#479=AXIS2_PLACEMENT_3D('',#476,#477,#478);
#480=CIRCLE('',#479,2.75);
#481=CARTESIAN_POINT('',(17.,0.,91.25));
#482=VERTEX_POINT('',#481);
#483=EDGE_CURVE('E466',#473,#482,#480,.F.);
#484=ORIENTED_EDGE('',*,*,#483,.T.);
#485=DIRECTION('',(-1.,0.,0.));
#486=VECTOR('',#485,1.);
#487=CARTESIAN_POINT('',(0.,0.,91.25));
#488=LINE('',#487,#486);
#489=CARTESIAN_POINT('',(3.,0.,91.25));
#490=VERTEX_POINT('',#489);
#491=EDGE_CURVE('E464',#482,#490,#488,.T.);
#492=ORIENTED_EDGE('',*,*,#491,.T.);
#493=CARTESIAN_POINT('',(3.,0.,88.5));
#494=DIRECTION('',(0.,1.,0.));
#495=DIRECTION('',(0.,0.,1.));
#496=AXIS2_PLACEMENT_3D('',#493,#494,#495);
#497=CIRCLE('',#496,2.75);
#498=CARTESIAN_POINT('',(0.25,0.,88.5));
#499=VERTEX_POINT('',#498);
#500=EDGE_CURVE('E462',#490,#499,#497,.F.);
#501=ORIENTED_EDGE('',*,*,#500,.T.);
#502=DIRECTION('',(0.,0.,-1.));
#503=VECTOR('',#502,1.);
#504=CARTESIAN_POINT('',(0.25,0.,3.));
#505=LINE('',#504,#503);
#506=EDGE_CURVE('E460',#499,#446,#505,.T.);
#507=ORIENTED_EDGE('',*,*,#506,.T.);
#508=EDGE_LOOP('',(#450,#458,#467,#475,#484,#492,#501,#507));
#509=FACE_BOUND('',#508,.T.);
#510=ADVANCED_FACE('F532',(#404,#440,#509),#368,.F.);
#511=CARTESIAN_POINT('',(19.,3.,3.));
#512=DIRECTION('',(-0.978147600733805,-0.207911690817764,0.));
#513=DIRECTION('',(0.207911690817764,-0.978147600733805,0.));
#514=AXIS2_PLACEMENT_3D('',#511,#512,#513);
#515=PLANE('',#514);
#516=DIRECTION('',(-0.0427289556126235,0.201023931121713,-0.978653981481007));
#517=VECTOR('',#516,1.);
#518=CARTESIAN_POINT('',(19.,3.,3.));
#519=LINE('',#518,#517);
#520=CARTESIAN_POINT('',(19.,3.,3.));
#521=VERTEX_POINT('',#520);
#522=EDGE_CURVE('E549',#521,#29,#519,.T.);
#523=ORIENTED_EDGE('',*,*,#522,.T.);
#524=ORIENTED_EDGE('',*,*,#32,.T.);
#525=CARTESIAN_POINT('',(18.3512820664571,6.05197792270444,6.));
#526=DIRECTION('',(-0.978147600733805,-0.207911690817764,0.));
#527=DIRECTION('',(-0.207911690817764,0.978147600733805,0.));
#528=AXIS2_PLACEMENT_3D('',#525,#526,#527);
#529=ELLIPSE('',#528,5.87845842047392,5.75);
#530=CARTESIAN_POINT('',(18.3512820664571,6.05197792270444,0.25));
#531=VERTEX_POINT('',#530);
#532=EDGE_CURVE('E672',#31,#531,#529,.F.);
#533=ORIENTED_EDGE('',*,*,#532,.T.);
#534=DIRECTION('',(-0.207911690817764,0.978147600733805,0.));
#535=VECTOR('',#534,1.);
#536=CARTESIAN_POINT('',(16.1401837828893,16.4543774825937,0.25));
#537=LINE('',#536,#535);
#538=CARTESIAN_POINT('',(16.1401837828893,16.4543774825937,0.25));
#539=VERTEX_POINT('',#538);
#540=EDGE_CURVE('E669',#531,#539,#537,.T.);
#541=ORIENTED_EDGE('',*,*,#540,.T.);
#542=DIRECTION('',(0.,0.,-1.));
#543=VECTOR('',#542,1.);
#544=CARTESIAN_POINT('',(16.1401837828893,16.4543774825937,3.));
#545=LINE('',#544,#543);
#546=CARTESIAN_POINT('',(16.1401837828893,16.4543774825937,2.75));
#547=VERTEX_POINT('',#546);
#548=EDGE_CURVE('E426',#547,#539,#545,.T.);
#549=ORIENTED_EDGE('',*,*,#548,.F.);
#550=CARTESIAN_POINT('',(16.0679259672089,16.7943237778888,2.75));
#551=DIRECTION('',(-0.978147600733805,-0.207911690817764,0.));
#552=DIRECTION('',(-0.207911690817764,0.978147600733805,0.));
#553=AXIS2_PLACEMENT_3D('',#550,#551,#552);
#554=ELLIPSE('',#553,0.347540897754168,0.25);
#555=CARTESIAN_POINT('',(16.0679259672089,16.7943237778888,3.));
#556=VERTEX_POINT('',#555);
#557=EDGE_CURVE('E11',#547,#556,#554,.T.);
#558=ORIENTED_EDGE('',*,*,#557,.T.);
#559=DIRECTION('',(-0.207911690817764,0.978147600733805,0.));
#560=VECTOR('',#559,1.);
#561=CARTESIAN_POINT('',(19.,3.,3.));
#562=LINE('',#561,#560);
#563=CARTESIAN_POINT('',(18.3623303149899,6.,3.));
#564=VERTEX_POINT('',#563);
#565=EDGE_CURVE('E410',#564,#556,#562,.T.);
#566=ORIENTED_EDGE('',*,*,#565,.F.);
#567=CARTESIAN_POINT('',(18.3623303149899,6.,6.));
#568=DIRECTION('',(-0.978147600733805,-0.207911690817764,0.));
#569=DIRECTION('',(0.207911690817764,-0.978147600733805,0.));
#570=AXIS2_PLACEMENT_3D('',#567,#568,#569);
#571=ELLIPSE('',#570,3.06702178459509,3.);
#572=CARTESIAN_POINT('',(19.,3.,6.00000000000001));
#573=VERTEX_POINT('',#572);
#574=EDGE_CURVE('E574',#564,#573,#571,.T.);
#575=ORIENTED_EDGE('',*,*,#574,.T.);
#576=DIRECTION('',(0.,0.,1.));
#577=VECTOR('',#576,1.);
#578=CARTESIAN_POINT('',(19.,3.,91.5));
#579=LINE('',#578,#577);
#580=EDGE_CURVE('E553',#521,#573,#579,.T.);
#581=ORIENTED_EDGE('',*,*,#580,.F.);
#582=EDGE_LOOP('',(#523,#524,#533,#541,#549,#558,#566,#575,#581));
#583=FACE_BOUND('',#582,.T.);
#584=ADVANCED_FACE('F390',(#583),#515,.F.);
#585=CARTESIAN_POINT('',(18.5,19.9529488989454,3.));
#586=DIRECTION('',(-0.829037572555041,0.559192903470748,0.));
#587=DIRECTION('',(-0.559192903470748,-0.829037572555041,0.));
#588=AXIS2_PLACEMENT_3D('',#585,#586,#587);
#589=PLANE('',#588);
#590=DIRECTION('',(0.,0.,-1.));
#591=VECTOR('',#590,1.);
#592=CARTESIAN_POINT('',(18.5,19.9529488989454,3.));
#593=LINE('',#592,#591);
#594=CARTESIAN_POINT('',(18.5,19.9529488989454,2.75));
#595=VERTEX_POINT('',#594);
#596=CARTESIAN_POINT('',(18.5,19.9529488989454,0.25));
#597=VERTEX_POINT('',#596);
#598=EDGE_CURVE('E424',#595,#597,#593,.T.);
#599=ORIENTED_EDGE('',*,*,#598,.F.);
#600=DIRECTION('',(0.559192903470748,0.829037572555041,0.));
#601=VECTOR('',#600,1.);
#602=CARTESIAN_POINT('',(18.5,19.9529488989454,2.75));
#603=LINE('',#602,#601);
#604=EDGE_CURVE('E42',#595,#547,#603,.F.);
#605=ORIENTED_EDGE('',*,*,#604,.T.);
#606=ORIENTED_EDGE('',*,*,#548,.T.);
#607=DIRECTION('',(0.559192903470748,0.829037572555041,0.));
#608=VECTOR('',#607,1.);
#609=CARTESIAN_POINT('',(18.5,19.9529488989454,0.25));
#610=LINE('',#609,#608);
#611=EDGE_CURVE('E616',#539,#597,#610,.T.);
#612=ORIENTED_EDGE('',*,*,#611,.T.);
#613=EDGE_LOOP('',(#599,#605,#606,#612));
#614=FACE_BOUND('',#613,.T.);
#615=ADVANCED_FACE('F604',(#614),#589,.F.);
#616=CARTESIAN_POINT('',(12.5,24.,3.));
#617=DIRECTION('',(-0.559192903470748,-0.829037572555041,0.));
#618=DIRECTION('',(0.829037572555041,-0.559192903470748,0.));
#619=AXIS2_PLACEMENT_3D('',#616,#617,#618);
#620=PLANE('',#619);
#621=DIRECTION('',(0.,0.,-1.));
#622=VECTOR('',#621,1.);
#623=CARTESIAN_POINT('',(12.5,24.,3.));
#624=LINE('',#623,#622);
#625=CARTESIAN_POINT('',(12.5,24.,2.75));
#626=VERTEX_POINT('',#625);
#627=CARTESIAN_POINT('',(12.5,24.,0.25));
#628=VERTEX_POINT('',#627);
#629=EDGE_CURVE('E422',#626,#628,#624,.T.);
#630=ORIENTED_EDGE('',*,*,#629,.F.);
#631=DIRECTION('',(-0.829037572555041,0.559192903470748,0.));
#632=VECTOR('',#631,1.);
#633=CARTESIAN_POINT('',(12.5,24.,2.75));
#634=LINE('',#633,#632);
#635=EDGE_CURVE('E590',#626,#595,#634,.F.);
#636=ORIENTED_EDGE('',*,*,#635,.T.);
#637=ORIENTED_EDGE('',*,*,#598,.T.);
#638=DIRECTION('',(-0.829037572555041,0.559192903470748,0.));
#639=VECTOR('',#638,1.);
#640=CARTESIAN_POINT('',(12.5,24.,0.25));
#641=LINE('',#640,#639);
#642=EDGE_CURVE('E558',#597,#628,#641,.T.);
#643=ORIENTED_EDGE('',*,*,#642,.T.);
#644=EDGE_LOOP('',(#630,#636,#637,#643));
#645=FACE_BOUND('',#644,.T.);
#646=ADVANCED_FACE('F600',(#645),#620,.F.);
#647=CARTESIAN_POINT('',(15.,9.20980054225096,3.));
#648=DIRECTION('',(0.,0.,-1.));
#649=DIRECTION('',(-1.,0.,0.));
#650=AXIS2_PLACEMENT_3D('',#647,#648,#649);
#651=CYLINDRICAL_SURFACE('',#650,15.);
#652=CARTESIAN_POINT('',(15.,9.20980054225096,3.));
#653=DIRECTION('',(0.,0.,1.));
#654=DIRECTION('',(-1.,0.,0.));
#655=AXIS2_PLACEMENT_3D('',#652,#653,#654);
#656=CIRCLE('',#655,15.);
#657=CARTESIAN_POINT('',(12.1476519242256,23.9361072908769,3.));
#658=VERTEX_POINT('',#657);
#659=CARTESIAN_POINT('',(0.,9.20980054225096,3.));
#660=VERTEX_POINT('',#659);
#661=EDGE_CURVE('E414',#658,#660,#656,.T.);
#662=ORIENTED_EDGE('',*,*,#661,.F.);
#663=CARTESIAN_POINT('',(12.1476519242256,23.9361072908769,3.));
#664=CARTESIAN_POINT('',(12.1745416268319,23.9413193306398,2.99995738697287));
#665=CARTESIAN_POINT('',(12.2015335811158,23.9464673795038,2.99774375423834));
#666=CARTESIAN_POINT('',(12.2550494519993,23.9565278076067,2.98868470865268));
#667=CARTESIAN_POINT('',(12.2815660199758,23.9614373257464,2.98179334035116));
#668=CARTESIAN_POINT('',(12.3252504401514,23.9694095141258,2.96586351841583));
#669=CARTESIAN_POINT('',(12.3428525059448,23.9725870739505,2.95807389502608));
#670=CARTESIAN_POINT('',(12.3766675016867,23.9786331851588,2.93987360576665));
#671=CARTESIAN_POINT('',(12.3928849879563,23.9815027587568,2.929472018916));
#672=CARTESIAN_POINT('',(12.4190263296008,23.9860889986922,2.90909670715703));
#673=CARTESIAN_POINT('',(12.4294537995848,23.9879055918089,2.89979332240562));
#674=CARTESIAN_POINT('',(12.4487695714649,23.9912523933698,2.87964625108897));
#675=CARTESIAN_POINT('',(12.4576594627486,23.9927828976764,2.86880417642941));
#676=CARTESIAN_POINT('',(12.4716762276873,23.9951858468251,2.84810019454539));
#677=CARTESIAN_POINT('',(12.4772013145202,23.9961290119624,2.83851726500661));
#678=CARTESIAN_POINT('',(12.4866232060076,23.9977334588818,2.81856981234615));
#679=CARTESIAN_POINT('',(12.4905238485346,23.9983954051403,2.80820720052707));
#680=CARTESIAN_POINT('',(12.4956070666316,23.9992569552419,2.78985663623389));
#681=CARTESIAN_POINT('',(12.4972415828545,23.9995335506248,2.78199620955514));
#682=CARTESIAN_POINT('',(12.4994439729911,23.9999060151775,2.76609399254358));
#683=CARTESIAN_POINT('',(12.5000078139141,24.0000012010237,2.75805163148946));
#684=CARTESIAN_POINT('',(12.5,24.,2.75));
#685=B_SPLINE_CURVE_WITH_KNOTS('',3,(#663,#664,#665,#666,#667,#668,#669,#670,#671,#672,#673,
#674,#675,#676,#677,#678,#679,#680,#681,#682,#683,#684),.UNSPECIFIED.,.F.,.F.,(4,2,2,2,2,2,2,2,
2,2,4),(0.,0.0822386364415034,0.165297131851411,0.223643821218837,0.281790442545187,
0.323931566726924,0.366028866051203,0.399207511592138,0.432307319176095,0.456335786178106,
0.480454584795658),.UNSPECIFIED.);
#686=EDGE_CURVE('E583',#658,#626,#685,.T.);
#687=ORIENTED_EDGE('',*,*,#686,.T.);
#688=ORIENTED_EDGE('',*,*,#629,.T.);
#689=CARTESIAN_POINT('',(15.,9.20980054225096,0.25));
#690=DIRECTION('',(0.,0.,-1.));
#691=DIRECTION('',(-1.,0.,0.));
#692=AXIS2_PLACEMENT_3D('',#689,#690,#691);
#693=CIRCLE('',#692,15.);
#694=CARTESIAN_POINT('',(0.,9.20980054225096,0.25));
#695=VERTEX_POINT('',#694);
#696=EDGE_CURVE('E556',#628,#695,#693,.F.);
#697=ORIENTED_EDGE('',*,*,#696,.T.);
#698=DIRECTION('',(0.,0.,-1.));
#699=VECTOR('',#698,1.);
#700=CARTESIAN_POINT('',(0.,9.20980054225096,3.));
#701=LINE('',#700,#699);
#702=EDGE_CURVE('E419',#660,#695,#701,.T.);
#703=ORIENTED_EDGE('',*,*,#702,.F.);
#704=EDGE_LOOP('',(#662,#687,#688,#697,#703));
#705=FACE_BOUND('',#704,.T.);
#706=ADVANCED_FACE('F594',(#705),#651,.T.);
#707=CARTESIAN_POINT('',(0.,0.,3.));
#708=DIRECTION('',(1.,0.,0.));
#709=DIRECTION('',(0.,0.,-1.));
#710=AXIS2_PLACEMENT_3D('',#707,#708,#709);
#711=PLANE('',#710);
#712=CARTESIAN_POINT('',(0.,6.,6.));
#713=DIRECTION('',(1.,0.,0.));
#714=DIRECTION('',(0.,0.,-1.));
#715=AXIS2_PLACEMENT_3D('',#712,#713,#714);
#716=CIRCLE('',#715,5.75);
#717=CARTESIAN_POINT('',(0.,6.,0.25));
#718=VERTEX_POINT('',#717);
#719=CARTESIAN_POINT('',(0.,0.25,6.));
#720=VERTEX_POINT('',#719);
#721=EDGE_CURVE('E665',#718,#720,#716,.F.);
#722=ORIENTED_EDGE('',*,*,#721,.T.);
#723=DIRECTION('',(0.,0.,-1.));
#724=VECTOR('',#723,1.);
#725=CARTESIAN_POINT('',(0.,0.25,3.));
#726=LINE('',#725,#724);
#727=CARTESIAN_POINT('',(0.,0.25,88.5));
#728=VERTEX_POINT('',#727);
#729=EDGE_CURVE('E667',#720,#728,#726,.F.);
#730=ORIENTED_EDGE('',*,*,#729,.T.);
#731=DIRECTION('',(0.,1.,0.));
#732=VECTOR('',#731,1.);
#733=CARTESIAN_POINT('',(0.,0.,88.5));
#734=LINE('',#733,#732);
#735=CARTESIAN_POINT('',(0.,3.,88.5));
#736=VERTEX_POINT('',#735);
#737=EDGE_CURVE('E428',#728,#736,#734,.T.);
#738=ORIENTED_EDGE('',*,*,#737,.T.);
#739=DIRECTION('',(0.,0.,-1.));
#740=VECTOR('',#739,1.);
#741=CARTESIAN_POINT('',(0.,3.,91.5));
#742=LINE('',#741,#740);
#743=CARTESIAN_POINT('',(0.,3.,6.00000000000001));
#744=VERTEX_POINT('',#743);
#745=EDGE_CURVE('E406',#736,#744,#742,.T.);
#746=ORIENTED_EDGE('',*,*,#745,.T.);
#747=CARTESIAN_POINT('',(0.,6.,6.));
#748=DIRECTION('',(1.,0.,0.));
#749=DIRECTION('',(0.,0.,-1.));
#750=AXIS2_PLACEMENT_3D('',#747,#748,#749);
#751=CIRCLE('',#750,3.);
#752=CARTESIAN_POINT('',(0.,6.,3.));
#753=VERTEX_POINT('',#752);
#754=EDGE_CURVE('E576',#744,#753,#751,.T.);
#755=ORIENTED_EDGE('',*,*,#754,.T.);
#756=DIRECTION('',(0.,-1.,0.));
#757=VECTOR('',#756,1.);
#758=CARTESIAN_POINT('',(0.,0.,3.));
#759=LINE('',#758,#757);
#760=EDGE_CURVE('E416',#660,#753,#759,.T.);
#761=ORIENTED_EDGE('',*,*,#760,.F.);
#762=ORIENTED_EDGE('',*,*,#702,.T.);
#763=DIRECTION('',(0.,-1.,0.));
#764=VECTOR('',#763,1.);
#765=CARTESIAN_POINT('',(0.,6.,0.25));
#766=LINE('',#765,#764);
#767=EDGE_CURVE('E663',#695,#718,#766,.T.);
#768=ORIENTED_EDGE('',*,*,#767,.T.);
#769=EDGE_LOOP('',(#722,#730,#738,#746,#755,#761,#762,#768));
#770=FACE_BOUND('',#769,.T.);
#771=ADVANCED_FACE('F599',(#770),#711,.F.);
#772=CARTESIAN_POINT('',(15.,9.20980054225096,3.));
#773=DIRECTION('',(0.,0.,-1.));
#774=DIRECTION('',(-1.,0.,0.));
#775=AXIS2_PLACEMENT_3D('',#772,#773,#774);
#776=PLANE('',#775);
#777=DIRECTION('',(0.559192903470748,0.829037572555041,0.));
#778=VECTOR('',#777,1.);
#779=CARTESIAN_POINT('',(12.2178652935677,11.0863740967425,3.));
#780=LINE('',#779,#778);
#781=CARTESIAN_POINT('',(18.1529423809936,19.8854877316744,3.));
#782=VERTEX_POINT('',#781);
#783=EDGE_CURVE('E578',#556,#782,#780,.T.);
#784=ORIENTED_EDGE('',*,*,#783,.T.);
#785=DIRECTION('',(-0.829037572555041,0.559192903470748,0.));
#786=VECTOR('',#785,1.);
#787=CARTESIAN_POINT('',(20.9350770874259,18.0089141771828,3.));
#788=LINE('',#787,#786);
#789=EDGE_CURVE('E580',#782,#658,#788,.T.);
#790=ORIENTED_EDGE('',*,*,#789,.T.);
#791=ORIENTED_EDGE('',*,*,#661,.T.);
#792=ORIENTED_EDGE('',*,*,#760,.T.);
#793=DIRECTION('',(1.,0.,0.));
#794=VECTOR('',#793,1.);
#795=CARTESIAN_POINT('',(15.,6.,3.));
#796=LINE('',#795,#794);
#797=EDGE_CURVE('E568',#753,#564,#796,.T.);
#798=ORIENTED_EDGE('',*,*,#797,.T.);
#799=ORIENTED_EDGE('',*,*,#565,.T.);
#800=EDGE_LOOP('',(#784,#790,#791,#792,#798,#799));
#801=FACE_BOUND('',#800,.T.);
#802=ADVANCED_FACE('F629',(#801),#776,.F.);
#803=CARTESIAN_POINT('',(15.,9.20980054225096,0.));
#804=DIRECTION('',(0.,0.,-1.));
#805=DIRECTION('',(-1.,0.,0.));
#806=AXIS2_PLACEMENT_3D('',#803,#804,#805);
#807=PLANE('',#806);
#808=DIRECTION('',(1.,0.,0.));
#809=VECTOR('',#808,1.);
#810=CARTESIAN_POINT('',(0.,6.,0.));
#811=LINE('',#810,#809);
#812=CARTESIAN_POINT('',(18.1067451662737,6.,0.));
#813=VERTEX_POINT('',#812);
#814=CARTESIAN_POINT('',(0.25,6.,0.));
#815=VERTEX_POINT('',#814);
#816=EDGE_CURVE('E457',#813,#815,#811,.F.);
#817=ORIENTED_EDGE('',*,*,#816,.T.);
#818=DIRECTION('',(0.,-1.,0.));
#819=VECTOR('',#818,1.);
#820=CARTESIAN_POINT('',(0.25,9.20980054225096,0.));
#821=LINE('',#820,#819);
#822=CARTESIAN_POINT('',(0.25,9.20980054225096,0.));
#823=VERTEX_POINT('',#822);
#824=EDGE_CURVE('E868',#815,#823,#821,.F.);
#825=ORIENTED_EDGE('',*,*,#824,.T.);
#826=CARTESIAN_POINT('',(15.,9.20980054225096,0.));
#827=DIRECTION('',(0.,0.,-1.));
#828=DIRECTION('',(-1.,0.,0.));
#829=AXIS2_PLACEMENT_3D('',#826,#827,#828);
#830=CIRCLE('',#829,14.75);
#831=CARTESIAN_POINT('',(12.4434916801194,23.7365608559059,0.));
#832=VERTEX_POINT('',#831);
#833=EDGE_CURVE('E873',#823,#832,#830,.T.);
#834=ORIENTED_EDGE('',*,*,#833,.T.);
#835=DIRECTION('',(-0.829037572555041,0.559192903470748,0.));
#836=VECTOR('',#835,1.);
#837=CARTESIAN_POINT('',(18.3602017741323,19.7456895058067,0.));
#838=LINE('',#837,#836);
#839=CARTESIAN_POINT('',(18.1529423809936,19.8854877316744,0.));
#840=VERTEX_POINT('',#839);
#841=EDGE_CURVE('E875',#832,#840,#838,.F.);
#842=ORIENTED_EDGE('',*,*,#841,.T.);
#843=DIRECTION('',(0.559192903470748,0.829037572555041,0.));
#844=VECTOR('',#843,1.);
#845=CARTESIAN_POINT('',(15.9329243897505,16.5941757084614,0.));
#846=LINE('',#845,#844);
#847=CARTESIAN_POINT('',(15.8735835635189,16.5061993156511,0.));
#848=VERTEX_POINT('',#847);
#849=EDGE_CURVE('E879',#840,#848,#846,.F.);
#850=ORIENTED_EDGE('',*,*,#849,.T.);
#851=DIRECTION('',(-0.207911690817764,0.978147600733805,0.));
#852=VECTOR('',#851,1.);
#853=CARTESIAN_POINT('',(18.1177934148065,5.94802207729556,0.));
#854=LINE('',#853,#852);
#855=EDGE_CURVE('E871',#848,#813,#854,.F.);
#856=ORIENTED_EDGE('',*,*,#855,.T.);
#857=EDGE_LOOP('',(#817,#825,#834,#842,#850,#856));
#858=FACE_BOUND('',#857,.T.);
#859=ADVANCED_FACE('F704',(#858),#807,.T.);
#860=CARTESIAN_POINT('',(0.,3.,91.5));
#861=DIRECTION('',(0.,1.,0.));
#862=DIRECTION('',(-1.,0.,0.));
#863=AXIS2_PLACEMENT_3D('',#860,#861,#862);
#864=PLANE('',#863);
#865=CARTESIAN_POINT('',(9.99999999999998,3.,87.));
#866=DIRECTION('',(0.,1.,0.));
#867=DIRECTION('',(-1.,0.,0.));
#868=AXIS2_PLACEMENT_3D('',#865,#866,#867);
#869=CIRCLE('',#868,1.75);
#870=CARTESIAN_POINT('',(8.24999999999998,3.,87.));
#871=VERTEX_POINT('',#870);
#872=CARTESIAN_POINT('',(11.75,3.,87.));
#873=VERTEX_POINT('',#872);
#874=EDGE_CURVE('E57',#871,#873,#869,.T.);
#875=ORIENTED_EDGE('',*,*,#874,.F.);
#876=DIRECTION('',(0.,0.,1.));
#877=VECTOR('',#876,1.);
#878=CARTESIAN_POINT('',(8.24999999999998,3.,87.));
#879=LINE('',#878,#877);
#880=CARTESIAN_POINT('',(8.24999999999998,3.,80.5));
#881=VERTEX_POINT('',#880);
#882=EDGE_CURVE('E273',#881,#871,#879,.T.);
#883=ORIENTED_EDGE('',*,*,#882,.F.);
#884=CARTESIAN_POINT('',(9.99999999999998,3.,80.5));
#885=DIRECTION('',(0.,1.,0.));
#886=DIRECTION('',(-1.,0.,0.));
#887=AXIS2_PLACEMENT_3D('',#884,#885,#886);
#888=CIRCLE('',#887,1.75);
#889=CARTESIAN_POINT('',(11.75,3.,80.5));
#890=VERTEX_POINT('',#889);
#891=EDGE_CURVE('E257',#890,#881,#888,.T.);
#892=ORIENTED_EDGE('',*,*,#891,.F.);
#893=DIRECTION('',(0.,0.,-1.));
#894=VECTOR('',#893,1.);
#895=CARTESIAN_POINT('',(11.75,3.,80.5));
#896=LINE('',#895,#894);
#897=EDGE_CURVE('E266',#873,#890,#896,.T.);
#898=ORIENTED_EDGE('',*,*,#897,.F.);
#899=EDGE_LOOP('',(#875,#883,#892,#898));
#900=FACE_BOUND('',#899,.T.);
#901=CARTESIAN_POINT('',(9.99999999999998,3.,47.));
#902=DIRECTION('',(0.,1.,0.));
#903=DIRECTION('',(-1.,0.,0.));
#904=AXIS2_PLACEMENT_3D('',#901,#902,#903);
#905=CIRCLE('',#904,1.75);
#906=CARTESIAN_POINT('',(8.24999999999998,3.,47.));
#907=VERTEX_POINT('',#906);
#908=CARTESIAN_POINT('',(11.75,3.,47.));
#909=VERTEX_POINT('',#908);
#910=EDGE_CURVE('E289',#907,#909,#905,.T.);
#911=ORIENTED_EDGE('',*,*,#910,.F.);
#912=DIRECTION('',(0.,0.,1.));
#913=VECTOR('',#912,1.);
#914=CARTESIAN_POINT('',(8.24999999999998,3.,47.));
#915=LINE('',#914,#913);
#916=CARTESIAN_POINT('',(8.24999999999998,3.,40.5));
#917=VERTEX_POINT('',#916);
#918=EDGE_CURVE('E299',#917,#907,#915,.T.);
#919=ORIENTED_EDGE('',*,*,#918,.F.);
#920=CARTESIAN_POINT('',(9.99999999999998,3.,40.5));
#921=DIRECTION('',(0.,1.,0.));
#922=DIRECTION('',(-1.,0.,0.));
#923=AXIS2_PLACEMENT_3D('',#920,#921,#922);
#924=CIRCLE('',#923,1.75);
#925=CARTESIAN_POINT('',(11.75,3.,40.5));
#926=VERTEX_POINT('',#925);
#927=EDGE_CURVE('E296',#926,#917,#924,.T.);
#928=ORIENTED_EDGE('',*,*,#927,.F.);
#929=DIRECTION('',(0.,0.,-1.));
#930=VECTOR('',#929,1.);
#931=CARTESIAN_POINT('',(11.75,3.,40.5));
#932=LINE('',#931,#930);
#933=EDGE_CURVE('E293',#909,#926,#932,.T.);
#934=ORIENTED_EDGE('',*,*,#933,.F.);
#935=EDGE_LOOP('',(#911,#919,#928,#934));
#936=FACE_BOUND('',#935,.T.);
#937=DIRECTION('',(0.0436193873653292,0.,0.999048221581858));
#938=VECTOR('',#937,1.);
#939=CARTESIAN_POINT('',(19.,3.,3.));
#940=LINE('',#939,#938);
#941=CARTESIAN_POINT('',(19.9904822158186,3.,25.6857724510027));
#942=VERTEX_POINT('',#941);
#943=EDGE_CURVE('E397',#521,#942,#940,.T.);
#944=ORIENTED_EDGE('',*,*,#943,.F.);
#945=ORIENTED_EDGE('',*,*,#580,.T.);
#946=DIRECTION('',(1.,0.,0.));
#947=VECTOR('',#946,1.);
#948=CARTESIAN_POINT('',(0.,3.,6.00000000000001));
#949=LINE('',#948,#947);
#950=EDGE_CURVE('E571',#573,#744,#949,.F.);
#951=ORIENTED_EDGE('',*,*,#950,.T.);
#952=ORIENTED_EDGE('',*,*,#745,.F.);
#953=CARTESIAN_POINT('',(3.,3.,88.5));
#954=DIRECTION('',(0.,1.,0.));
#955=DIRECTION('',(-1.,0.,0.));
#956=AXIS2_PLACEMENT_3D('',#953,#954,#955);
#957=CIRCLE('',#956,3.);
#958=CARTESIAN_POINT('',(3.,3.,91.5));
#959=VERTEX_POINT('',#958);
#960=EDGE_CURVE('E432',#736,#959,#957,.T.);
#961=ORIENTED_EDGE('',*,*,#960,.T.);
#962=DIRECTION('',(1.,0.,0.));
#963=VECTOR('',#962,1.);
#964=CARTESIAN_POINT('',(0.,3.,91.5));
#965=LINE('',#964,#963);
#966=CARTESIAN_POINT('',(17.,3.,91.5));
#967=VERTEX_POINT('',#966);
#968=EDGE_CURVE('E403',#959,#967,#965,.T.);
#969=ORIENTED_EDGE('',*,*,#968,.T.);
#970=CARTESIAN_POINT('',(17.,3.,88.5));
#971=DIRECTION('',(0.,1.,0.));
#972=DIRECTION('',(-1.,0.,0.));
#973=AXIS2_PLACEMENT_3D('',#970,#971,#972);
#974=CIRCLE('',#973,3.);
#975=CARTESIAN_POINT('',(20.,3.,88.5));
#976=VERTEX_POINT('',#975);
#977=EDGE_CURVE('E430',#967,#976,#974,.T.);
#978=ORIENTED_EDGE('',*,*,#977,.T.);
#979=DIRECTION('',(0.,0.,-1.));
#980=VECTOR('',#979,1.);
#981=CARTESIAN_POINT('',(20.,3.,91.5));
#982=LINE('',#981,#980);
#983=CARTESIAN_POINT('',(20.,3.,26.121966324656));
#984=VERTEX_POINT('',#983);
#985=EDGE_CURVE('E407',#976,#984,#982,.T.);
#986=ORIENTED_EDGE('',*,*,#985,.T.);
#987=CARTESIAN_POINT('',(10.,3.,26.121966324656));
#988=DIRECTION('',(0.,1.,0.));
#989=DIRECTION('',(-1.,0.,0.));
#990=AXIS2_PLACEMENT_3D('',#987,#988,#989);
#991=CIRCLE('',#990,10.);
#992=EDGE_CURVE('E447',#984,#942,#991,.T.);
#993=ORIENTED_EDGE('',*,*,#992,.T.);
#994=EDGE_LOOP('',(#944,#945,#951,#952,#961,#969,#978,#986,#993));
#995=FACE_BOUND('',#994,.T.);
#996=ADVANCED_FACE('F270',(#900,#936,#995),#864,.T.);
#997=CARTESIAN_POINT('',(20.,0.,91.5));
#998=DIRECTION('',(1.,0.,0.));
#999=DIRECTION('',(0.,0.,-1.));
#1000=AXIS2_PLACEMENT_3D('',#997,#998,#999);
#1001=PLANE('',#1000);
#1002=DIRECTION('',(0.,-1.,0.));
#1003=VECTOR('',#1002,1.);
#1004=CARTESIAN_POINT('',(20.,0.,88.5));
#1005=LINE('',#1004,#1003);
#1006=CARTESIAN_POINT('',(20.,0.25,88.5));
#1007=VERTEX_POINT('',#1006);
#1008=EDGE_CURVE('E439',#976,#1007,#1005,.T.);
#1009=ORIENTED_EDGE('',*,*,#1008,.T.);
#1010=DIRECTION('',(0.,0.,-1.));
#1011=VECTOR('',#1010,1.);
#1012=CARTESIAN_POINT('',(20.,0.25,26.121966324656));
#1013=LINE('',#1012,#1011);
#1014=CARTESIAN_POINT('',(20.,0.25,26.121966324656));
#1015=VERTEX_POINT('',#1014);
#1016=EDGE_CURVE('E653',#1007,#1015,#1013,.T.);
#1017=ORIENTED_EDGE('',*,*,#1016,.T.);
#1018=DIRECTION('',(0.,-1.,0.));
#1019=VECTOR('',#1018,1.);
#1020=CARTESIAN_POINT('',(20.,3.,26.121966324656));
#1021=LINE('',#1020,#1019);
#1022=EDGE_CURVE('E445',#1015,#984,#1021,.F.);
#1023=ORIENTED_EDGE('',*,*,#1022,.T.);
#1024=ORIENTED_EDGE('',*,*,#985,.F.);
#1025=EDGE_LOOP('',(#1009,#1017,#1023,#1024));
#1026=FACE_BOUND('',#1025,.T.);
#1027=ADVANCED_FACE('F698',(#1026),#1001,.T.);
#1028=CARTESIAN_POINT('',(0.,0.,91.5));
#1029=DIRECTION('',(0.,0.,-1.));
#1030=DIRECTION('',(-1.,0.,0.));
#1031=AXIS2_PLACEMENT_3D('',#1028,#1029,#1030);
#1032=PLANE('',#1031);
#1033=DIRECTION('',(0.,1.,0.));
#1034=VECTOR('',#1033,1.);
#1035=CARTESIAN_POINT('',(3.,0.,91.5));
#1036=LINE('',#1035,#1034);
#1037=CARTESIAN_POINT('',(3.,0.25,91.5));
#1038=VERTEX_POINT('',#1037);
#1039=EDGE_CURVE('E436',#959,#1038,#1036,.F.);
#1040=ORIENTED_EDGE('',*,*,#1039,.T.);
#1041=DIRECTION('',(-1.,0.,0.));
#1042=VECTOR('',#1041,1.);
#1043=CARTESIAN_POINT('',(0.,0.25,91.5));
#1044=LINE('',#1043,#1042);
#1045=CARTESIAN_POINT('',(17.,0.25,91.5));
#1046=VERTEX_POINT('',#1045);
#1047=EDGE_CURVE('E657',#1038,#1046,#1044,.F.);
#1048=ORIENTED_EDGE('',*,*,#1047,.T.);
#1049=DIRECTION('',(0.,-1.,0.));
#1050=VECTOR('',#1049,1.);
#1051=CARTESIAN_POINT('',(17.,3.,91.5));
#1052=LINE('',#1051,#1050);
#1053=EDGE_CURVE('E434',#1046,#967,#1052,.F.);
#1054=ORIENTED_EDGE('',*,*,#1053,.T.);
#1055=ORIENTED_EDGE('',*,*,#968,.F.);
#1056=EDGE_LOOP('',(#1040,#1048,#1054,#1055));
#1057=FACE_BOUND('',#1056,.T.);
#1058=ADVANCED_FACE('F694',(#1057),#1032,.F.);
#1059=CARTESIAN_POINT('',(3.,0.,88.5));
#1060=DIRECTION('',(0.,1.,0.));
#1061=DIRECTION('',(0.,0.,1.));
#1062=AXIS2_PLACEMENT_3D('',#1059,#1060,#1061);
#1063=CYLINDRICAL_SURFACE('',#1062,3.);
#1064=ORIENTED_EDGE('',*,*,#737,.F.);
#1065=CARTESIAN_POINT('',(3.,0.25,88.5));
#1066=DIRECTION('',(0.,1.,0.));
#1067=DIRECTION('',(0.,0.,1.));
#1068=AXIS2_PLACEMENT_3D('',#1065,#1066,#1067);
#1069=CIRCLE('',#1068,3.);
#1070=EDGE_CURVE('E661',#728,#1038,#1069,.T.);
#1071=ORIENTED_EDGE('',*,*,#1070,.T.);
#1072=ORIENTED_EDGE('',*,*,#1039,.F.);
#1073=ORIENTED_EDGE('',*,*,#960,.F.);
#1074=EDGE_LOOP('',(#1064,#1071,#1072,#1073));
#1075=FACE_BOUND('',#1074,.T.);
#1076=ADVANCED_FACE('F690',(#1075),#1063,.T.);
#1077=CARTESIAN_POINT('',(17.,0.,88.5));
#1078=DIRECTION('',(0.,1.,0.));
#1079=DIRECTION('',(0.,0.,1.));
#1080=AXIS2_PLACEMENT_3D('',#1077,#1078,#1079);
#1081=CYLINDRICAL_SURFACE('',#1080,3.);
#1082=ORIENTED_EDGE('',*,*,#1053,.F.);
#1083=CARTESIAN_POINT('',(17.,0.25,88.5));
#1084=DIRECTION('',(0.,1.,0.));
#1085=DIRECTION('',(0.,0.,1.));
#1086=AXIS2_PLACEMENT_3D('',#1083,#1084,#1085);
#1087=CIRCLE('',#1086,3.);
#1088=EDGE_CURVE('E654',#1046,#1007,#1087,.T.);
#1089=ORIENTED_EDGE('',*,*,#1088,.T.);
#1090=ORIENTED_EDGE('',*,*,#1008,.F.);
#1091=ORIENTED_EDGE('',*,*,#977,.F.);
#1092=EDGE_LOOP('',(#1082,#1089,#1090,#1091));
#1093=FACE_BOUND('',#1092,.T.);
#1094=ADVANCED_FACE('F687',(#1093),#1081,.T.);
#1095=CARTESIAN_POINT('',(19.,0.,3.));
#1096=DIRECTION('',(-0.999048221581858,0.,0.0436193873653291));
#1097=DIRECTION('',(0.0436193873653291,0.,0.999048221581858));
#1098=AXIS2_PLACEMENT_3D('',#1095,#1096,#1097);
#1099=PLANE('',#1098);
#1100=DIRECTION('',(0.,-1.,0.));
#1101=VECTOR('',#1100,1.);
#1102=CARTESIAN_POINT('',(19.9904822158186,0.,25.6857724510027));
#1103=LINE('',#1102,#1101);
#1104=CARTESIAN_POINT('',(19.9904822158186,0.25,25.6857724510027));
#1105=VERTEX_POINT('',#1104);
#1106=EDGE_CURVE('E442',#942,#1105,#1103,.T.);
#1107=ORIENTED_EDGE('',*,*,#1106,.T.);
#1108=DIRECTION('',(0.0436193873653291,0.,0.999048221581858));
#1109=VECTOR('',#1108,1.);
#1110=CARTESIAN_POINT('',(19.,0.25,3.));
#1111=LINE('',#1110,#1109);
#1112=CARTESIAN_POINT('',(19.0561517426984,0.25,4.28608634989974));
#1113=VERTEX_POINT('',#1112);
#1114=EDGE_CURVE('E475',#1105,#1113,#1111,.F.);
#1115=ORIENTED_EDGE('',*,*,#1114,.T.);
#1116=CARTESIAN_POINT('',(19.1309828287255,6.,6.));
#1117=DIRECTION('',(-0.999048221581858,0.,0.0436193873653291));
#1118=DIRECTION('',(-0.0436193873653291,0.,-0.999048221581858));
#1119=AXIS2_PLACEMENT_3D('',#1116,#1117,#1118);
#1120=ELLIPSE('',#1119,6.00571611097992,6.);
#1121=CARTESIAN_POINT('',(19.,0.803847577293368,3.));
#1122=VERTEX_POINT('',#1121);
#1123=EDGE_CURVE('E452',#1113,#1122,#1120,.F.);
#1124=ORIENTED_EDGE('',*,*,#1123,.T.);
#1125=DIRECTION('',(0.,1.,0.));
#1126=VECTOR('',#1125,1.);
#1127=CARTESIAN_POINT('',(19.,0.,3.));
#1128=LINE('',#1127,#1126);
#1129=EDGE_CURVE('E400',#1122,#40,#1128,.T.);
#1130=ORIENTED_EDGE('',*,*,#1129,.T.);
#1131=ORIENTED_EDGE('',*,*,#41,.F.);
#1132=ORIENTED_EDGE('',*,*,#522,.F.);
#1133=ORIENTED_EDGE('',*,*,#943,.T.);
#1134=EDGE_LOOP('',(#1107,#1115,#1124,#1130,#1131,#1132,#1133));
#1135=FACE_BOUND('',#1134,.T.);
#1136=ADVANCED_FACE('F645',(#1135),#1099,.F.);
#1137=CARTESIAN_POINT('',(19.,0.,3.));
#1138=DIRECTION('',(-1.,0.,0.));
#1139=DIRECTION('',(0.,-1.,0.));
#1140=AXIS2_PLACEMENT_3D('',#1137,#1138,#1139);
#1141=PLANE('',#1140);
#1142=CARTESIAN_POINT('',(19.,1.61485191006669,1.90482280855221));
#1143=CARTESIAN_POINT('',(19.,1.67184989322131,1.84382475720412));
#1144=CARTESIAN_POINT('',(19.,1.73068853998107,1.78450482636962));
#1145=CARTESIAN_POINT('',(19.,1.85211050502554,1.66967417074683));
#1146=CARTESIAN_POINT('',(19.,1.91469853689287,1.61416843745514));
#1147=CARTESIAN_POINT('',(19.,2.03403239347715,1.51544118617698));
#1148=CARTESIAN_POINT('',(19.,2.09027788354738,1.47161546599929));
#1149=CARTESIAN_POINT('',(19.,2.205454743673,1.38767445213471));
#1150=CARTESIAN_POINT('',(19.,2.26438482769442,1.34755740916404));
#1151=CARTESIAN_POINT('',(19.,2.36170454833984,1.28649447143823));
#1152=CARTESIAN_POINT('',(19.,2.39921131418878,1.26414053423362));
#1153=CARTESIAN_POINT('',(19.,2.47535044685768,1.22144857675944));
#1154=CARTESIAN_POINT('',(19.,2.51398268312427,1.20111032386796));
#1155=CARTESIAN_POINT('',(19.,2.60134204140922,1.15860886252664));
#1156=CARTESIAN_POINT('',(19.,2.65038241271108,1.13706701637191));
#1157=CARTESIAN_POINT('',(19.,2.73194107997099,1.10684563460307));
#1158=CARTESIAN_POINT('',(19.,2.7637775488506,1.09636902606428));
#1159=CARTESIAN_POINT('',(19.,2.81711704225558,1.08228152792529));
#1160=CARTESIAN_POINT('',(19.,2.83830358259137,1.07755239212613));
#1161=CARTESIAN_POINT('',(19.,2.87083103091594,1.07250397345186));
#1162=CARTESIAN_POINT('',(19.,2.88200937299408,1.07115764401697));
#1163=CARTESIAN_POINT('',(19.,2.90443721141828,1.06957702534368));
#1164=CARTESIAN_POINT('',(19.,2.91568634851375,1.06933906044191));
#1165=CARTESIAN_POINT('',(19.,2.93149353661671,1.07034016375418));
#1166=CARTESIAN_POINT('',(19.,2.9360980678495,1.07079327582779));
#1167=CARTESIAN_POINT('',(19.,2.94526193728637,1.07211973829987));
#1168=CARTESIAN_POINT('',(19.,2.94982114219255,1.07299408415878));
#1169=CARTESIAN_POINT('',(19.,2.95886343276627,1.07532953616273));
#1170=CARTESIAN_POINT('',(19.,2.96334447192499,1.07679892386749));
#1171=CARTESIAN_POINT('',(19.,2.97197212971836,1.08051739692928));
#1172=CARTESIAN_POINT('',(19.,2.97612035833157,1.08276240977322));
#1173=CARTESIAN_POINT('',(19.,2.9820679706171,1.08703811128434));
#1174=CARTESIAN_POINT('',(19.,2.98410415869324,1.08873722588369));
#1175=CARTESIAN_POINT('',(19.,2.98786888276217,1.09244419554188));
#1176=CARTESIAN_POINT('',(19.,2.98959810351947,1.09445134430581));
#1177=CARTESIAN_POINT('',(19.,2.99267409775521,1.09874989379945));
#1178=CARTESIAN_POINT('',(19.,2.99401973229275,1.10104211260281));
#1179=CARTESIAN_POINT('',(19.,2.99629286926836,1.10583464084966));
#1180=CARTESIAN_POINT('',(19.,2.99721872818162,1.10833572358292));
#1181=CARTESIAN_POINT('',(19.,2.99866761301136,1.11348636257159));
#1182=CARTESIAN_POINT('',(19.,2.99918466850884,1.11613753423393));
#1183=CARTESIAN_POINT('',(19.,2.99984999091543,1.12146771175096));
#1184=CARTESIAN_POINT('',(19.,3.00000090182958,1.12414637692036));
#1185=CARTESIAN_POINT('',(19.,3.00000000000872,1.12681513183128));
#1186=B_SPLINE_CURVE_WITH_KNOTS('',3,(#1142,#1143,#1144,#1145,#1146,#1147,#1148,#1149,#1150,
#1151,#1152,#1153,#1154,#1155,#1156,#1157,#1158,#1159,#1160,#1161,#1162,#1163,#1164,#1165,#1166,
#1167,#1168,#1169,#1170,#1171,#1172,#1173,#1174,#1175,#1176,#1177,#1178,#1179,#1180,#1181,#1182,
#1183,#1184,#1185),.UNSPECIFIED.,.F.,.F.,(4,2,2,2,2,2,2,2,2,2,2,2,2,2,2,2,2,2,2,2,2,4),(0.,
0.250462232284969,0.501246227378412,0.715032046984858,0.928716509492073,1.05965291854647,
1.19057419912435,1.35099477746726,1.45140602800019,1.5163962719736,1.55014734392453,
1.58378640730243,1.59765313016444,1.61155278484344,1.62565292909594,1.63968013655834,
1.64760556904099,1.65551309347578,1.66344385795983,1.67140541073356,1.67948119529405,
1.6874984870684),.UNSPECIFIED.);
#1187=CARTESIAN_POINT('',(19.,1.61485191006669,1.90482280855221));
#1188=VERTEX_POINT('',#1187);
#1189=EDGE_CURVE('E673',#1188,#48,#1186,.T.);
#1190=ORIENTED_EDGE('',*,*,#1189,.T.);
#1191=ORIENTED_EDGE('',*,*,#49,.T.);
#1192=ORIENTED_EDGE('',*,*,#1129,.F.);
#1193=CARTESIAN_POINT('',(19.,6.,6.));
#1194=DIRECTION('',(-1.,0.,0.));
#1195=DIRECTION('',(0.,-1.,0.));
#1196=AXIS2_PLACEMENT_3D('',#1193,#1194,#1195);
#1197=CIRCLE('',#1196,6.);
#1198=EDGE_CURVE('E454',#1122,#1188,#1197,.F.);
#1199=ORIENTED_EDGE('',*,*,#1198,.T.);
#1200=EDGE_LOOP('',(#1190,#1191,#1192,#1199));
#1201=FACE_BOUND('',#1200,.T.);
#1202=ADVANCED_FACE('F681',(#1201),#1141,.F.);
#1203=CARTESIAN_POINT('',(10.,0.,26.121966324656));
#1204=DIRECTION('',(0.,1.,0.));
#1205=DIRECTION('',(0.,0.,1.));
#1206=AXIS2_PLACEMENT_3D('',#1203,#1204,#1205);
#1207=CYLINDRICAL_SURFACE('',#1206,10.);
#1208=ORIENTED_EDGE('',*,*,#1022,.F.);
#1209=CARTESIAN_POINT('',(10.,0.25,26.121966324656));
#1210=DIRECTION('',(0.,1.,0.));
#1211=DIRECTION('',(0.,0.,1.));
#1212=AXIS2_PLACEMENT_3D('',#1209,#1210,#1211);
#1213=CIRCLE('',#1212,10.);
#1214=EDGE_CURVE('E487',#1015,#1105,#1213,.T.);
#1215=ORIENTED_EDGE('',*,*,#1214,.T.);
#1216=ORIENTED_EDGE('',*,*,#1106,.F.);
#1217=ORIENTED_EDGE('',*,*,#992,.F.);
#1218=EDGE_LOOP('',(#1208,#1215,#1216,#1217));
#1219=FACE_BOUND('',#1218,.T.);
#1220=ADVANCED_FACE('F649',(#1219),#1207,.T.);
#1221=CARTESIAN_POINT('',(0.,6.,6.));
#1222=DIRECTION('',(-1.,0.,0.));
#1223=DIRECTION('',(0.,0.,1.));
#1224=AXIS2_PLACEMENT_3D('',#1221,#1222,#1223);
#1225=CYLINDRICAL_SURFACE('',#1224,6.);
#1226=ORIENTED_EDGE('',*,*,#1123,.F.);
#1227=CARTESIAN_POINT('',(19.0561517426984,0.25,4.28608634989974));
#1228=CARTESIAN_POINT('',(19.0578900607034,0.238052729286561,4.32616617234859));
#1229=CARTESIAN_POINT('',(19.0588023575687,0.226519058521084,4.36639328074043));
#1230=CARTESIAN_POINT('',(19.0592221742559,0.204298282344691,4.44707057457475));
#1231=CARTESIAN_POINT('',(19.0587303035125,0.19361081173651,4.48752065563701));
#1232=CARTESIAN_POINT('',(19.0555217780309,0.162848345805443,4.60908483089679));
#1233=CARTESIAN_POINT('',(19.0510742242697,0.144053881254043,4.69047801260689));
#1234=CARTESIAN_POINT('',(19.0375040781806,0.106034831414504,4.87232152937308));
#1235=CARTESIAN_POINT('',(19.0275473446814,0.0876874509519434,4.97288960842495));
#1236=CARTESIAN_POINT('',(19.0043505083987,0.0561869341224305,5.17446757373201));
#1237=CARTESIAN_POINT('',(18.9911090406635,0.0430359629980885,5.27547762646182));
#1238=CARTESIAN_POINT('',(18.9483436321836,0.0113350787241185,5.57897414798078));
#1239=CARTESIAN_POINT('',(18.915778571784,0.00053696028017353,5.78192810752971));
#1240=CARTESIAN_POINT('',(18.8823843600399,6.5091872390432E-06,5.98979359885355));
#1241=CARTESIAN_POINT('',(18.881564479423,-1.35525765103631E-09,5.99489686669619));
#1242=CARTESIAN_POINT('',(18.8807446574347,0.,6.00000000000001));
#1243=B_SPLINE_CURVE_WITH_KNOTS('',3,(#1227,#1228,#1229,#1230,#1231,#1232,#1233,#1234,#1235,
#1236,#1237,#1238,#1239,#1240,#1241,#1242),.UNSPECIFIED.,.F.,.F.,(4,2,2,2,2,2,2,4),(0.,
0.125548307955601,0.251042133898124,0.501826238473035,0.80973551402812,1.11777295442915,
1.73384438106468,1.74935049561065),.UNSPECIFIED.);
#1244=EDGE_CURVE('E481',#1113,#448,#1243,.T.);
#1245=ORIENTED_EDGE('',*,*,#1244,.T.);
#1246=ORIENTED_EDGE('',*,*,#449,.F.);
#1247=CARTESIAN_POINT('',(0.25,6.,6.));
#1248=DIRECTION('',(1.,0.,0.));
#1249=DIRECTION('',(0.,0.,-1.));
#1250=AXIS2_PLACEMENT_3D('',#1247,#1248,#1249);
#1251=CIRCLE('',#1250,6.);
#1252=EDGE_CURVE('E479',#446,#815,#1251,.T.);
#1253=ORIENTED_EDGE('',*,*,#1252,.T.);
#1254=ORIENTED_EDGE('',*,*,#816,.F.);
#1255=CARTESIAN_POINT('',(18.1067451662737,6.,6.));
#1256=DIRECTION('',(0.979877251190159,0.199601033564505,0.));
#1257=DIRECTION('',(-0.199601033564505,0.979877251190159,0.));
#1258=AXIS2_PLACEMENT_3D('',#1255,#1256,#1257);
#1259=ELLIPSE('',#1258,6.12321593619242,6.);
#1260=EDGE_CURVE('E477',#813,#1188,#1259,.F.);
#1261=ORIENTED_EDGE('',*,*,#1260,.T.);
#1262=ORIENTED_EDGE('',*,*,#1198,.F.);
#1263=EDGE_LOOP('',(#1226,#1245,#1246,#1253,#1254,#1261,#1262));
#1264=FACE_BOUND('',#1263,.T.);
#1265=ADVANCED_FACE('F384',(#1264),#1225,.T.);
#1266=ORIENTED_EDGE('',*,*,#532,.F.);
#1267=ORIENTED_EDGE('',*,*,#359,.T.);
#1268=ORIENTED_EDGE('',*,*,#1189,.F.);
#1269=ORIENTED_EDGE('',*,*,#1260,.F.);
#1270=CARTESIAN_POINT('',(18.1067451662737,6.,0.25));
#1271=DIRECTION('',(-0.207911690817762,0.978147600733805,0.));
#1272=DIRECTION('',(-0.978147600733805,-0.207911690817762,0.));
#1273=AXIS2_PLACEMENT_3D('',#1270,#1271,#1272);
#1274=CIRCLE('',#1273,0.25);
#1275=EDGE_CURVE('E396',#531,#813,#1274,.T.);
#1276=ORIENTED_EDGE('',*,*,#1275,.F.);
#1277=EDGE_LOOP('',(#1266,#1267,#1268,#1269,#1276));
#1278=FACE_BOUND('',#1277,.T.);
#1279=ADVANCED_FACE('F377',(#1278),#345,.T.);
#1280=CARTESIAN_POINT('',(18.7554630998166,2.94802207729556,0.25));
#1281=DIRECTION('',(0.207911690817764,-0.978147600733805,0.));
#1282=DIRECTION('',(0.978147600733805,0.207911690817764,0.));
#1283=AXIS2_PLACEMENT_3D('',#1280,#1281,#1282);
#1284=CYLINDRICAL_SURFACE('',#1283,0.25);
#1285=ORIENTED_EDGE('',*,*,#1275,.T.);
#1286=ORIENTED_EDGE('',*,*,#855,.F.);
#1287=CARTESIAN_POINT('',(15.8735835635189,16.5061993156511,0.25));
#1288=DIRECTION('',(-0.190808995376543,-0.981627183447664,0.));
#1289=DIRECTION('',(-0.981627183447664,0.190808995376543,0.));
#1290=AXIS2_PLACEMENT_3D('',#1287,#1288,#1289);
#1291=ELLIPSE('',#1290,0.271590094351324,0.25);
#1292=EDGE_CURVE('E887',#539,#848,#1291,.F.);
#1293=ORIENTED_EDGE('',*,*,#1292,.F.);
#1294=ORIENTED_EDGE('',*,*,#540,.F.);
#1295=EDGE_LOOP('',(#1285,#1286,#1293,#1294));
#1296=FACE_BOUND('',#1295,.T.);
#1297=ADVANCED_FACE('F373',(#1296),#1284,.T.);
#1298=CARTESIAN_POINT('',(18.2927406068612,20.0927471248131,0.25));
#1299=DIRECTION('',(-0.559192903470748,-0.829037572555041,0.));
#1300=DIRECTION('',(0.829037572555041,-0.559192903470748,0.));
#1301=AXIS2_PLACEMENT_3D('',#1298,#1299,#1300);
#1302=CYLINDRICAL_SURFACE('',#1301,0.25);
#1303=ORIENTED_EDGE('',*,*,#1292,.T.);
#1304=ORIENTED_EDGE('',*,*,#849,.F.);
#1305=CARTESIAN_POINT('',(18.1529423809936,19.8854877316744,0.25));
#1306=DIRECTION('',(0.190808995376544,-0.981627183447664,0.));
#1307=DIRECTION('',(0.981627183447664,0.190808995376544,0.));
#1308=AXIS2_PLACEMENT_3D('',#1305,#1306,#1307);
#1309=ELLIPSE('',#1308,0.353553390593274,0.25);
#1310=EDGE_CURVE('E360',#597,#840,#1309,.F.);
#1311=ORIENTED_EDGE('',*,*,#1310,.F.);
#1312=ORIENTED_EDGE('',*,*,#611,.F.);
#1313=EDGE_LOOP('',(#1303,#1304,#1311,#1312));
#1314=FACE_BOUND('',#1313,.T.);
#1315=ADVANCED_FACE('F369',(#1314),#1302,.T.);
#1316=CARTESIAN_POINT('',(12.3602017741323,23.7927406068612,0.25));
#1317=DIRECTION('',(0.829037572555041,-0.559192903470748,0.));
#1318=DIRECTION('',(0.559192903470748,0.829037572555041,0.));
#1319=AXIS2_PLACEMENT_3D('',#1316,#1317,#1318);
#1320=CYLINDRICAL_SURFACE('',#1319,0.25);
#1321=ORIENTED_EDGE('',*,*,#1310,.T.);
#1322=ORIENTED_EDGE('',*,*,#841,.F.);
#1323=CARTESIAN_POINT('',(12.5,24.,0.25));
#1324=CARTESIAN_POINT('',(12.5000034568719,24.0000155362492,0.236659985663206));
#1325=CARTESIAN_POINT('',(12.4997571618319,23.9988771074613,0.22332933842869));
#1326=CARTESIAN_POINT('',(12.4987920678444,23.9944138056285,0.197092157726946));
#1327=CARTESIAN_POINT('',(12.4980745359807,23.9910947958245,0.184184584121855));
#1328=CARTESIAN_POINT('',(12.4961939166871,23.9823916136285,0.159126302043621));
#1329=CARTESIAN_POINT('',(12.4950309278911,23.9770078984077,0.146975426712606));
#1330=CARTESIAN_POINT('',(12.4923045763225,23.9643784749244,0.123731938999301));
#1331=CARTESIAN_POINT('',(12.4907410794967,23.9571321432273,0.112639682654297));
#1332=CARTESIAN_POINT('',(12.487216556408,23.9407835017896,0.0914599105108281));
#1333=CARTESIAN_POINT('',(12.4852452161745,23.9316329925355,0.0814114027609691));
#1334=CARTESIAN_POINT('',(12.48099931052,23.9119048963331,0.0629059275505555));
#1335=CARTESIAN_POINT('',(12.4787246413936,23.9013268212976,0.0544495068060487));
#1336=CARTESIAN_POINT('',(12.4737750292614,23.878283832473,0.0387599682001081));
#1337=CARTESIAN_POINT('',(12.471083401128,23.8657396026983,0.0316487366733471));
#1338=CARTESIAN_POINT('',(12.4655061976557,23.8397140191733,0.0195246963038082));
#1339=CARTESIAN_POINT('',(12.4626205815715,23.8262324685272,0.0145123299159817));
#1340=CARTESIAN_POINT('',(12.4571648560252,23.8007092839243,0.00723327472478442));
#1341=CARTESIAN_POINT('',(12.4546106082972,23.7887467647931,0.00467155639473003));
#1342=CARTESIAN_POINT('',(12.44946351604,23.7646128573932,0.00115008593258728));
#1343=CARTESIAN_POINT('',(12.44687075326,23.7524419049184,0.000187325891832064));
#1344=CARTESIAN_POINT('',(12.4440180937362,23.7390352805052,8.23614597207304E-06));
#1345=CARTESIAN_POINT('',(12.4437548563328,23.7377979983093,-2.00012805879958E-08));
#1346=CARTESIAN_POINT('',(12.4434916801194,23.7365608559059,0.));
#1347=B_SPLINE_CURVE_WITH_KNOTS('',3,(#1323,#1324,#1325,#1326,#1327,#1328,#1329,#1330,#1331,
#1332,#1333,#1334,#1335,#1336,#1337,#1338,#1339,#1340,#1341,#1342,#1343,#1344,#1345,#1346),
.UNSPECIFIED.,.F.,.F.,(4,2,2,2,2,2,2,2,2,2,2,4),(0.,0.0399547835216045,0.0798025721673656,
0.119641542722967,0.159493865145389,0.200514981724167,0.241550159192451,0.285368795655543,
0.329196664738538,0.366591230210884,0.403915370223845,0.407710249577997),.UNSPECIFIED.);
#1348=EDGE_CURVE('E352',#628,#832,#1347,.T.);
#1349=ORIENTED_EDGE('',*,*,#1348,.F.);
#1350=ORIENTED_EDGE('',*,*,#642,.F.);
#1351=EDGE_LOOP('',(#1321,#1322,#1349,#1350));
#1352=FACE_BOUND('',#1351,.T.);
#1353=ADVANCED_FACE('F365',(#1352),#1320,.T.);
#1354=CARTESIAN_POINT('',(15.,9.20980054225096,0.25));
#1355=DIRECTION('',(0.,0.,-1.));
#1356=DIRECTION('',(-1.,0.,0.));
#1357=AXIS2_PLACEMENT_3D('',#1354,#1355,#1356);
#1358=TOROIDAL_SURFACE('',#1357,14.75,0.25);
#1359=ORIENTED_EDGE('',*,*,#1348,.T.);
#1360=ORIENTED_EDGE('',*,*,#833,.F.);
#1361=CARTESIAN_POINT('',(0.25,9.20980054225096,0.25));
#1362=DIRECTION('',(0.,-1.,0.));
#1363=DIRECTION('',(0.,0.,-1.));
#1364=AXIS2_PLACEMENT_3D('',#1361,#1362,#1363);
#1365=CIRCLE('',#1364,0.25);
#1366=EDGE_CURVE('E349',#695,#823,#1365,.T.);
#1367=ORIENTED_EDGE('',*,*,#1366,.F.);
#1368=ORIENTED_EDGE('',*,*,#696,.F.);
#1369=EDGE_LOOP('',(#1359,#1360,#1367,#1368));
#1370=FACE_BOUND('',#1369,.T.);
#1371=ADVANCED_FACE('F362',(#1370),#1358,.T.);
#1372=CARTESIAN_POINT('',(0.25,0.,0.25));
#1373=DIRECTION('',(0.,1.,0.));
#1374=DIRECTION('',(0.,0.,1.));
#1375=AXIS2_PLACEMENT_3D('',#1372,#1373,#1374);
#1376=CYLINDRICAL_SURFACE('',#1375,0.25);
#1377=ORIENTED_EDGE('',*,*,#1366,.T.);
#1378=ORIENTED_EDGE('',*,*,#824,.F.);
#1379=CARTESIAN_POINT('',(0.25,6.,0.25));
#1380=DIRECTION('',(0.,-1.,0.));
#1381=DIRECTION('',(0.,0.,-1.));
#1382=AXIS2_PLACEMENT_3D('',#1379,#1380,#1381);
#1383=CIRCLE('',#1382,0.25);
#1384=EDGE_CURVE('E346',#718,#815,#1383,.T.);
#1385=ORIENTED_EDGE('',*,*,#1384,.F.);
#1386=ORIENTED_EDGE('',*,*,#767,.F.);
#1387=EDGE_LOOP('',(#1377,#1378,#1385,#1386));
#1388=FACE_BOUND('',#1387,.T.);
#1389=ADVANCED_FACE('F523',(#1388),#1376,.T.);
#1390=CARTESIAN_POINT('',(0.25,6.,6.));
#1391=DIRECTION('',(1.,0.,0.));
#1392=DIRECTION('',(0.,0.,-1.));
#1393=AXIS2_PLACEMENT_3D('',#1390,#1391,#1392);
#1394=TOROIDAL_SURFACE('',#1393,5.75,0.25);
#1395=ORIENTED_EDGE('',*,*,#1384,.T.);
#1396=ORIENTED_EDGE('',*,*,#1252,.F.);
#1397=CARTESIAN_POINT('',(0.25,0.25,6.));
#1398=DIRECTION('',(0.,0.,1.));
#1399=DIRECTION('',(1.,0.,0.));
#1400=AXIS2_PLACEMENT_3D('',#1397,#1398,#1399);
#1401=CIRCLE('',#1400,0.25);
#1402=EDGE_CURVE('E343',#720,#446,#1401,.T.);
#1403=ORIENTED_EDGE('',*,*,#1402,.F.);
#1404=ORIENTED_EDGE('',*,*,#721,.F.);
#1405=EDGE_LOOP('',(#1395,#1396,#1403,#1404));
#1406=FACE_BOUND('',#1405,.T.);
#1407=ADVANCED_FACE('F520',(#1406),#1394,.T.);
#1408=CARTESIAN_POINT('',(0.25,0.25,3.));
#1409=DIRECTION('',(0.,0.,-1.));
#1410=DIRECTION('',(-1.,0.,0.));
#1411=AXIS2_PLACEMENT_3D('',#1408,#1409,#1410);
#1412=CYLINDRICAL_SURFACE('',#1411,0.25);
#1413=ORIENTED_EDGE('',*,*,#1402,.T.);
#1414=ORIENTED_EDGE('',*,*,#506,.F.);
#1415=CARTESIAN_POINT('',(0.25,0.25,88.5));
#1416=DIRECTION('',(0.,0.,1.));
#1417=DIRECTION('',(1.,0.,0.));
#1418=AXIS2_PLACEMENT_3D('',#1415,#1416,#1417);
#1419=CIRCLE('',#1418,0.25);
#1420=EDGE_CURVE('E340',#728,#499,#1419,.T.);
#1421=ORIENTED_EDGE('',*,*,#1420,.F.);
#1422=ORIENTED_EDGE('',*,*,#729,.F.);
#1423=EDGE_LOOP('',(#1413,#1414,#1421,#1422));
#1424=FACE_BOUND('',#1423,.T.);
#1425=ADVANCED_FACE('F516',(#1424),#1412,.T.);
#1426=CARTESIAN_POINT('',(3.,0.25,88.5));
#1427=DIRECTION('',(0.,1.,0.));
#1428=DIRECTION('',(0.,0.,1.));
#1429=AXIS2_PLACEMENT_3D('',#1426,#1427,#1428);
#1430=TOROIDAL_SURFACE('',#1429,2.75,0.25);
#1431=ORIENTED_EDGE('',*,*,#1420,.T.);
#1432=ORIENTED_EDGE('',*,*,#500,.F.);
#1433=CARTESIAN_POINT('',(3.,0.25,91.25));
#1434=DIRECTION('',(1.,0.,0.));
#1435=DIRECTION('',(0.,0.,-1.));
#1436=AXIS2_PLACEMENT_3D('',#1433,#1434,#1435);
#1437=CIRCLE('',#1436,0.25);
#1438=EDGE_CURVE('E337',#1038,#490,#1437,.T.);
#1439=ORIENTED_EDGE('',*,*,#1438,.F.);
#1440=ORIENTED_EDGE('',*,*,#1070,.F.);
#1441=EDGE_LOOP('',(#1431,#1432,#1439,#1440));
#1442=FACE_BOUND('',#1441,.T.);
#1443=ADVANCED_FACE('F512',(#1442),#1430,.T.);
#1444=CARTESIAN_POINT('',(0.,0.25,91.25));
#1445=DIRECTION('',(-1.,0.,0.));
#1446=DIRECTION('',(0.,0.,1.));
#1447=AXIS2_PLACEMENT_3D('',#1444,#1445,#1446);
#1448=CYLINDRICAL_SURFACE('',#1447,0.25);
#1449=ORIENTED_EDGE('',*,*,#1438,.T.);
#1450=ORIENTED_EDGE('',*,*,#491,.F.);
#1451=CARTESIAN_POINT('',(17.,0.25,91.25));
#1452=DIRECTION('',(1.,0.,0.));
#1453=DIRECTION('',(0.,0.,-1.));
#1454=AXIS2_PLACEMENT_3D('',#1451,#1452,#1453);
#1455=CIRCLE('',#1454,0.25);
#1456=EDGE_CURVE('E334',#1046,#482,#1455,.T.);
#1457=ORIENTED_EDGE('',*,*,#1456,.F.);
#1458=ORIENTED_EDGE('',*,*,#1047,.F.);
#1459=EDGE_LOOP('',(#1449,#1450,#1457,#1458));
#1460=FACE_BOUND('',#1459,.T.);
#1461=ADVANCED_FACE('F508',(#1460),#1448,.T.);
#1462=CARTESIAN_POINT('',(17.,0.25,88.5));
#1463=DIRECTION('',(0.,1.,0.));
#1464=DIRECTION('',(0.,0.,1.));
#1465=AXIS2_PLACEMENT_3D('',#1462,#1463,#1464);
#1466=TOROIDAL_SURFACE('',#1465,2.75,0.25);
#1467=ORIENTED_EDGE('',*,*,#1456,.T.);
#1468=ORIENTED_EDGE('',*,*,#483,.F.);
#1469=CARTESIAN_POINT('',(19.75,0.25,88.5));
#1470=DIRECTION('',(0.,0.,-1.));
#1471=DIRECTION('',(-1.,0.,0.));
#1472=AXIS2_PLACEMENT_3D('',#1469,#1470,#1471);
#1473=CIRCLE('',#1472,0.25);
#1474=EDGE_CURVE('E331',#1007,#473,#1473,.T.);
#1475=ORIENTED_EDGE('',*,*,#1474,.F.);
#1476=ORIENTED_EDGE('',*,*,#1088,.F.);
#1477=EDGE_LOOP('',(#1467,#1468,#1475,#1476));
#1478=FACE_BOUND('',#1477,.T.);
#1479=ADVANCED_FACE('F504',(#1478),#1466,.T.);
#1480=CARTESIAN_POINT('',(19.75,0.25,91.5));
#1481=DIRECTION('',(0.,0.,1.));
#1482=DIRECTION('',(1.,0.,0.));
#1483=AXIS2_PLACEMENT_3D('',#1480,#1481,#1482);
#1484=CYLINDRICAL_SURFACE('',#1483,0.25);
#1485=ORIENTED_EDGE('',*,*,#1474,.T.);
#1486=ORIENTED_EDGE('',*,*,#474,.F.);
#1487=CARTESIAN_POINT('',(19.75,0.25,26.121966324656));
#1488=DIRECTION('',(0.,0.,-1.));
#1489=DIRECTION('',(-1.,0.,0.));
#1490=AXIS2_PLACEMENT_3D('',#1487,#1488,#1489);
#1491=CIRCLE('',#1490,0.25);
#1492=EDGE_CURVE('E328',#1015,#465,#1491,.T.);
#1493=ORIENTED_EDGE('',*,*,#1492,.F.);
#1494=ORIENTED_EDGE('',*,*,#1016,.F.);
#1495=EDGE_LOOP('',(#1485,#1486,#1493,#1494));
#1496=FACE_BOUND('',#1495,.T.);
#1497=ADVANCED_FACE('F500',(#1496),#1484,.T.);
#1498=CARTESIAN_POINT('',(10.,0.25,26.121966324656));
#1499=DIRECTION('',(0.,1.,0.));
#1500=DIRECTION('',(0.,0.,1.));
#1501=AXIS2_PLACEMENT_3D('',#1498,#1499,#1500);
#1502=TOROIDAL_SURFACE('',#1501,9.75,0.25);
#1503=ORIENTED_EDGE('',*,*,#1492,.T.);
#1504=ORIENTED_EDGE('',*,*,#466,.F.);
#1505=CARTESIAN_POINT('',(19.7407201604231,0.25,25.6966772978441));
#1506=DIRECTION('',(-0.0436193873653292,0.,-0.999048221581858));
#1507=DIRECTION('',(-0.999048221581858,0.,0.0436193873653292));
#1508=AXIS2_PLACEMENT_3D('',#1505,#1506,#1507);
#1509=CIRCLE('',#1508,0.25);
#1510=EDGE_CURVE('E326',#1105,#456,#1509,.T.);
#1511=ORIENTED_EDGE('',*,*,#1510,.F.);
#1512=ORIENTED_EDGE('',*,*,#1214,.F.);
#1513=EDGE_LOOP('',(#1503,#1504,#1511,#1512));
#1514=FACE_BOUND('',#1513,.T.);
#1515=ADVANCED_FACE('F495',(#1514),#1502,.T.);
#1516=CARTESIAN_POINT('',(18.7140875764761,0.25,2.18292529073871));
#1517=DIRECTION('',(0.0436193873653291,0.,0.999048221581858));
#1518=DIRECTION('',(0.999048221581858,0.,-0.0436193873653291));
#1519=AXIS2_PLACEMENT_3D('',#1516,#1517,#1518);
#1520=CYLINDRICAL_SURFACE('',#1519,0.25);
#1521=ORIENTED_EDGE('',*,*,#1244,.F.);
#1522=ORIENTED_EDGE('',*,*,#1114,.F.);
#1523=ORIENTED_EDGE('',*,*,#1510,.T.);
#1524=ORIENTED_EDGE('',*,*,#457,.F.);
#1525=EDGE_LOOP('',(#1521,#1522,#1523,#1524));
#1526=FACE_BOUND('',#1525,.T.);
#1527=ADVANCED_FACE('F489',(#1526),#1520,.T.);
#1528=CARTESIAN_POINT('',(15.,6.,6.));
#1529=DIRECTION('',(1.,0.,0.));
#1530=DIRECTION('',(0.,1.,0.));
#1531=AXIS2_PLACEMENT_3D('',#1528,#1529,#1530);
#1532=CYLINDRICAL_SURFACE('',#1531,3.);
#1533=ORIENTED_EDGE('',*,*,#754,.F.);
#1534=ORIENTED_EDGE('',*,*,#950,.F.);
#1535=ORIENTED_EDGE('',*,*,#574,.F.);
#1536=ORIENTED_EDGE('',*,*,#797,.F.);
#1537=EDGE_LOOP('',(#1533,#1534,#1535,#1536));
#1538=FACE_BOUND('',#1537,.T.);
#1539=ADVANCED_FACE('F494',(#1538),#1532,.F.);
#1540=CARTESIAN_POINT('',(12.2178652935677,11.0863740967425,2.75));
#1541=DIRECTION('',(0.559192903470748,0.829037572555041,0.));
#1542=DIRECTION('',(-0.829037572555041,0.559192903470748,0.));
#1543=AXIS2_PLACEMENT_3D('',#1540,#1541,#1542);
#1544=CYLINDRICAL_SURFACE('',#1543,0.25);
#1545=ORIENTED_EDGE('',*,*,#557,.F.);
#1546=ORIENTED_EDGE('',*,*,#604,.F.);
#1547=CARTESIAN_POINT('',(18.1529423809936,19.8854877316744,2.75));
#1548=DIRECTION('',(-0.190808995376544,0.981627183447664,0.));
#1549=DIRECTION('',(0.981627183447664,0.190808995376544,0.));
#1550=AXIS2_PLACEMENT_3D('',#1547,#1548,#1549);
#1551=ELLIPSE('',#1550,0.353553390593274,0.25);
#1552=EDGE_CURVE('E317',#782,#595,#1551,.T.);
#1553=ORIENTED_EDGE('',*,*,#1552,.F.);
#1554=ORIENTED_EDGE('',*,*,#783,.F.);
#1555=EDGE_LOOP('',(#1545,#1546,#1553,#1554));
#1556=FACE_BOUND('',#1555,.T.);
#1557=ADVANCED_FACE('F622',(#1556),#1544,.T.);
#1558=CARTESIAN_POINT('',(20.9350770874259,18.0089141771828,2.75));
#1559=DIRECTION('',(-0.829037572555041,0.559192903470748,0.));
#1560=DIRECTION('',(-0.559192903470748,-0.829037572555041,0.));
#1561=AXIS2_PLACEMENT_3D('',#1558,#1559,#1560);
#1562=CYLINDRICAL_SURFACE('',#1561,0.25);
#1563=ORIENTED_EDGE('',*,*,#1552,.T.);
#1564=ORIENTED_EDGE('',*,*,#635,.F.);
#1565=ORIENTED_EDGE('',*,*,#686,.F.);
#1566=ORIENTED_EDGE('',*,*,#789,.F.);
#1567=EDGE_LOOP('',(#1563,#1564,#1565,#1566));
#1568=FACE_BOUND('',#1567,.T.);
#1569=ADVANCED_FACE('F591',(#1568),#1562,.T.);
#1570=CARTESIAN_POINT('',(9.99999999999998,0.,47.));
#1571=DIRECTION('',(0.,1.,0.));
#1572=DIRECTION('',(-1.,0.,0.));
#1573=AXIS2_PLACEMENT_3D('',#1570,#1571,#1572);
#1574=CYLINDRICAL_SURFACE('',#1573,1.75);
#1575=ORIENTED_EDGE('',*,*,#910,.T.);
#1576=DIRECTION('',(0.,1.,0.));
#1577=VECTOR('',#1576,1.);
#1578=CARTESIAN_POINT('',(11.75,0.,47.));
#1579=LINE('',#1578,#1577);
#1580=EDGE_CURVE('E314',#421,#909,#1579,.T.);
#1581=ORIENTED_EDGE('',*,*,#1580,.F.);
#1582=ORIENTED_EDGE('',*,*,#422,.F.);
#1583=DIRECTION('',(0.,1.,0.));
#1584=VECTOR('',#1583,1.);
#1585=CARTESIAN_POINT('',(8.24999999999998,0.,47.));
#1586=LINE('',#1585,#1584);
#1587=EDGE_CURVE('E315',#412,#907,#1586,.T.);
#1588=ORIENTED_EDGE('',*,*,#1587,.T.);
#1589=EDGE_LOOP('',(#1575,#1581,#1582,#1588));
#1590=FACE_BOUND('',#1589,.T.);
#1591=ADVANCED_FACE('F756',(#1590),#1574,.F.);
#1592=CARTESIAN_POINT('',(8.24999999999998,0.,47.));
#1593=DIRECTION('',(-1.,0.,0.));
#1594=DIRECTION('',(0.,0.,1.));
#1595=AXIS2_PLACEMENT_3D('',#1592,#1593,#1594);
#1596=PLANE('',#1595);
#1597=ORIENTED_EDGE('',*,*,#918,.T.);
#1598=ORIENTED_EDGE('',*,*,#1587,.F.);
#1599=ORIENTED_EDGE('',*,*,#413,.F.);
#1600=DIRECTION('',(0.,1.,0.));
#1601=VECTOR('',#1600,1.);
#1602=CARTESIAN_POINT('',(8.24999999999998,0.,40.5));
#1603=LINE('',#1602,#1601);
#1604=EDGE_CURVE('E318',#410,#917,#1603,.T.);
#1605=ORIENTED_EDGE('',*,*,#1604,.T.);
#1606=EDGE_LOOP('',(#1597,#1598,#1599,#1605));
#1607=FACE_BOUND('',#1606,.T.);
#1608=ADVANCED_FACE('F762',(#1607),#1596,.F.);
#1609=CARTESIAN_POINT('',(9.99999999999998,0.,40.5));
#1610=DIRECTION('',(0.,1.,0.));
#1611=DIRECTION('',(-1.,0.,0.));
#1612=AXIS2_PLACEMENT_3D('',#1609,#1610,#1611);
#1613=CYLINDRICAL_SURFACE('',#1612,1.75);
#1614=ORIENTED_EDGE('',*,*,#927,.T.);
#1615=ORIENTED_EDGE('',*,*,#1604,.F.);
#1616=ORIENTED_EDGE('',*,*,#437,.F.);
#1617=DIRECTION('',(0.,1.,0.));
#1618=VECTOR('',#1617,1.);
#1619=CARTESIAN_POINT('',(11.75,0.,40.5));
#1620=LINE('',#1619,#1618);
#1621=EDGE_CURVE('E320',#429,#926,#1620,.T.);
#1622=ORIENTED_EDGE('',*,*,#1621,.T.);
#1623=EDGE_LOOP('',(#1614,#1615,#1616,#1622));
#1624=FACE_BOUND('',#1623,.T.);
#1625=ADVANCED_FACE('F769',(#1624),#1613,.F.);
#1626=CARTESIAN_POINT('',(11.75,0.,40.5));
#1627=DIRECTION('',(1.,0.,0.));
#1628=DIRECTION('',(0.,0.,-1.));
#1629=AXIS2_PLACEMENT_3D('',#1626,#1627,#1628);
#1630=PLANE('',#1629);
#1631=ORIENTED_EDGE('',*,*,#933,.T.);
#1632=ORIENTED_EDGE('',*,*,#1621,.F.);
#1633=ORIENTED_EDGE('',*,*,#430,.F.);
#1634=ORIENTED_EDGE('',*,*,#1580,.T.);
#1635=EDGE_LOOP('',(#1631,#1632,#1633,#1634));
#1636=FACE_BOUND('',#1635,.T.);
#1637=ADVANCED_FACE('F777',(#1636),#1630,.F.);
#1638=CARTESIAN_POINT('',(9.99999999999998,0.,87.));
#1639=DIRECTION('',(0.,1.,0.));
#1640=DIRECTION('',(-1.,0.,0.));
#1641=AXIS2_PLACEMENT_3D('',#1638,#1639,#1640);
#1642=CYLINDRICAL_SURFACE('',#1641,1.75);
#1643=ORIENTED_EDGE('',*,*,#874,.T.);
#1644=DIRECTION('',(0.,1.,0.));
#1645=VECTOR('',#1644,1.);
#1646=CARTESIAN_POINT('',(11.75,0.,87.));
#1647=LINE('',#1646,#1645);
#1648=EDGE_CURVE('E263',#385,#873,#1647,.T.);
#1649=ORIENTED_EDGE('',*,*,#1648,.F.);
#1650=ORIENTED_EDGE('',*,*,#386,.F.);
#1651=DIRECTION('',(0.,1.,0.));
#1652=VECTOR('',#1651,1.);
#1653=CARTESIAN_POINT('',(8.24999999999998,0.,87.));
#1654=LINE('',#1653,#1652);
#1655=EDGE_CURVE('E287',#376,#871,#1654,.T.);
#1656=ORIENTED_EDGE('',*,*,#1655,.T.);
#1657=EDGE_LOOP('',(#1643,#1649,#1650,#1656));
#1658=FACE_BOUND('',#1657,.T.);
#1659=ADVANCED_FACE('F785',(#1658),#1642,.F.);
#1660=CARTESIAN_POINT('',(8.24999999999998,0.,87.));
#1661=DIRECTION('',(-1.,0.,0.));
#1662=DIRECTION('',(0.,0.,1.));
#1663=AXIS2_PLACEMENT_3D('',#1660,#1661,#1662);
#1664=PLANE('',#1663);
#1665=ORIENTED_EDGE('',*,*,#882,.T.);
#1666=ORIENTED_EDGE('',*,*,#1655,.F.);
#1667=ORIENTED_EDGE('',*,*,#377,.F.);
#1668=DIRECTION('',(0.,1.,0.));
#1669=VECTOR('',#1668,1.);
#1670=CARTESIAN_POINT('',(8.24999999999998,0.,80.5));
#1671=LINE('',#1670,#1669);
#1672=EDGE_CURVE('E262',#374,#881,#1671,.T.);
#1673=ORIENTED_EDGE('',*,*,#1672,.T.);
#1674=EDGE_LOOP('',(#1665,#1666,#1667,#1673));
#1675=FACE_BOUND('',#1674,.T.);
#1676=ADVANCED_FACE('F794',(#1675),#1664,.F.);
#1677=CARTESIAN_POINT('',(9.99999999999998,0.,80.5));
#1678=DIRECTION('',(0.,1.,0.));
#1679=DIRECTION('',(-1.,0.,0.));
#1680=AXIS2_PLACEMENT_3D('',#1677,#1678,#1679);
#1681=CYLINDRICAL_SURFACE('',#1680,1.75);
#1682=ORIENTED_EDGE('',*,*,#891,.T.);
#1683=ORIENTED_EDGE('',*,*,#1672,.F.);
#1684=ORIENTED_EDGE('',*,*,#401,.F.);
#1685=DIRECTION('',(0.,1.,0.));
#1686=VECTOR('',#1685,1.);
#1687=CARTESIAN_POINT('',(11.75,0.,80.5));
#1688=LINE('',#1687,#1686);
#1689=EDGE_CURVE('E253',#393,#890,#1688,.T.);
#1690=ORIENTED_EDGE('',*,*,#1689,.T.);
#1691=EDGE_LOOP('',(#1682,#1683,#1684,#1690));
#1692=FACE_BOUND('',#1691,.T.);
#1693=ADVANCED_FACE('F255',(#1692),#1681,.F.);
#1694=CARTESIAN_POINT('',(11.75,0.,80.5));
#1695=DIRECTION('',(1.,0.,0.));
#1696=DIRECTION('',(0.,0.,-1.));
#1697=AXIS2_PLACEMENT_3D('',#1694,#1695,#1696);
#1698=PLANE('',#1697);
#1699=ORIENTED_EDGE('',*,*,#897,.T.);
#1700=ORIENTED_EDGE('',*,*,#1689,.F.);
#1701=ORIENTED_EDGE('',*,*,#394,.F.);
#1702=ORIENTED_EDGE('',*,*,#1648,.T.);
#1703=EDGE_LOOP('',(#1699,#1700,#1701,#1702));
#1704=FACE_BOUND('',#1703,.T.);
#1705=ADVANCED_FACE('F267',(#1704),#1698,.F.);
#1706=CLOSED_SHELL('',(#363,#510,#584,#615,#646,#706,#771,#802,#859,#996,#1027,#1058,#1076,
#1094,#1136,#1202,#1220,#1265,#1279,#1297,#1315,#1353,#1371,#1389,#1407,#1425,#1443,#1461,#1479,
#1497,#1515,#1527,#1539,#1557,#1569,#1591,#1608,#1625,#1637,#1659,#1676,#1693,#1705));
#1707=MANIFOLD_SOLID_BREP('B2',#1706);
#1708=ADVANCED_BREP_SHAPE_REPRESENTATION('',(#18,#1707),#14);
#1709=SHAPE_DEFINITION_REPRESENTATION(#9,#1708);
ENDSEC;
END-ISO-10303-21;
